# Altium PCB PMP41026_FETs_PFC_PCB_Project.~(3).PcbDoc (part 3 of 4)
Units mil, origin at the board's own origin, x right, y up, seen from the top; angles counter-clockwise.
Board outline 2440.95 x 1417.32 mil, 6 copper layers (Top Layer, Signal Layer 1, Signal Layer 2, Signal Layer 3, Signal Layer 4, Bottom Layer), stack 69.8 mil thick; 61 components, 66 nets, 254 pads, 775 vias.
Unrouted connection lines stored in the file: 2.

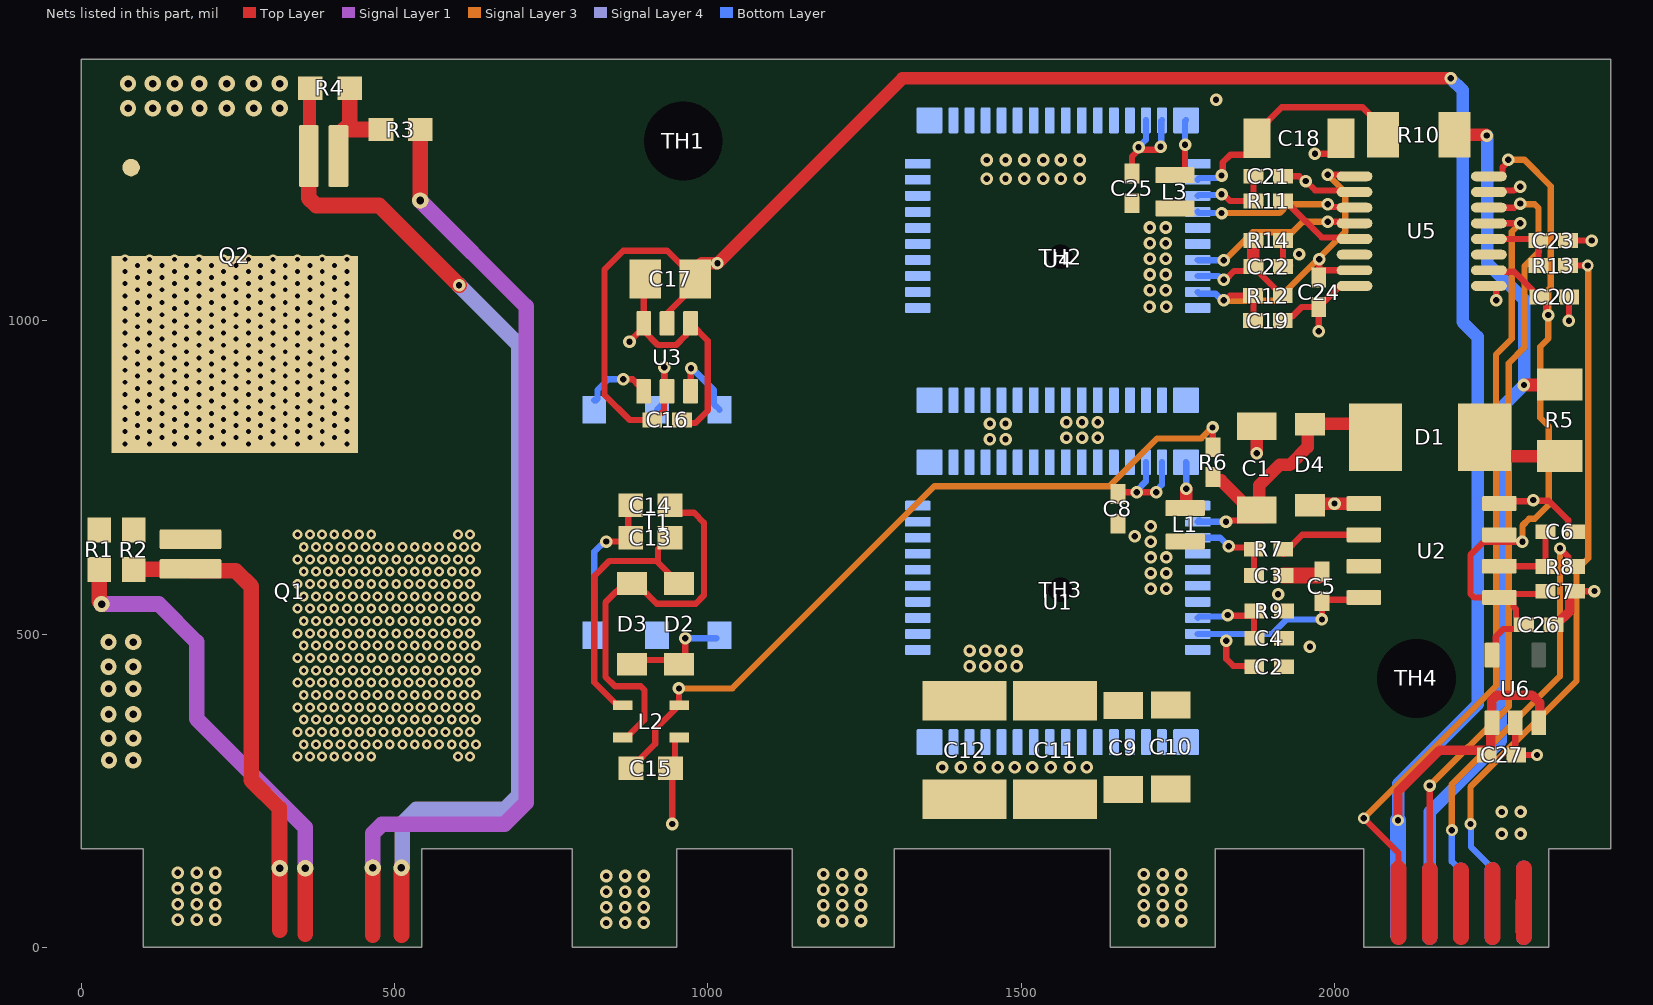
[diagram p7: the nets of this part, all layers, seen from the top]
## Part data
C1 C18: library part CMP-0008692-2, "CAP, CERM, 10 uF, 25 V, +/- 20%, X7R, 1206_190", Cap_Case=1206, Manufacturer=TDK, Supplier Part Number 1=445-6812-1-ND, TempCo=X7R, Tolerance_%=20%, Value1=Unknown, Value2=25V, ValueDisplayed=10uF
C2 C19: library part CMP-0860563-1, "CAP, CERM, 0.22 µF, 16 V,+/- 10%, X7R, 0402", Cap_Case=0402, Manufacturer="Samsung Electro-Mechanics", TempCo=X7R, Tolerance_%=10%, Value2=16V, ValueDisplayed=0.22µF
C3 C4 C6 C21 C22 C23: library part CMP-0006196-2, "CAP, CERM, 100 pF, 50 V, +/- 1%, C0G/NP0, 0402", Cap_Case=0402, Manufacturer=AVX, Supplier Part Number 1=478-3658-1-ND, TempCo=C0G/NP0, Tolerance_%=1%, Value1=Unknown, Value2=50V, ValueDisplayed=100pF
C5 C16 C24: library part CMP-0006297-2, "CAP, CERM, 0.1 uF, 50 V, +/- 10%, X7R, 0402", Alternate Manufacturer="Wurth Elektronik", Alternate PartNumber=885012205037, Cap_Case=0402, Manufacturer=TDK, Supplier Part Number 1=445-5932-1-ND, TempCo=X7R, Tolerance_%=10%, Value1="0.039064 ohm", Value2=50V, ValueDisplayed=0.1uF
C7 C20: library part CMP-0006276-2, "CAP, CERM, 1 uF, 25 V, +/- 10%, X5R, 0402", Alternate Manufacturer=TDK, Alternate PartNumber=C1005X5R1E225K050BC, Cap_Case=0402, Supplier Part Number 1=445-9066-1-ND, TempCo=X5R, Tolerance_%=10%, Value1=Unknown, Value2=25V, ValueDisplayed=1uF
C8 C25: library part CMP-0006716-2, "CAP, CERM, 2.2 uF, 25 V, +/- 10%, X5R, AEC-Q200 Grade 3, 0402", Cap_Case=0402, Manufacturer=MuRata, Supplier Part Number 1=490-12267-1-ND, TempCo=X5R, Tolerance_%=10%, Value1=Unknown, Value2=25V, ValueDisplayed=2.2uF
C9 C10: library part CMP-0084048-1, "CAP, CERM, 0.022 µF, 1000 V,+/- 10%, X7R, AEC-Q200 Grade 1, 1206", Cap_Case=1206, Manufacturer=Kemet, TempCo=X7R, Tolerance_%=10%, Value2=1000V, ValueDisplayed=0.022µF
C11 C12: library part CMP-0009326-2, "CAP, CERM, 0.1 uF, 1000 V, +/- 10%, X7R, 1812", Cap_Case=1812, Manufacturer=Kemet, Supplier Part Number 1=399-6523-1-ND, TempCo=X7R, Tolerance_%=10%, Value1=Unknown, Value2=1000V, ValueDisplayed=0.1uF
C13 C14 C15: library part CMP-0007022-5, "CAP, CERM, 4.7 uF, 35 V, +/- 10%, X5R, 0603", Cap_Case=0603, Manufacturer=TDK, Supplier Part Number 1=445-9064-1-ND, TempCo=X5R, Tolerance_%=10%, Value1="0.003728 ohm", Value2=35V, ValueDisplayed=4.7uF
C17: library part CMP-0008020-2, "CAP, CERM, 4.7 uF, 16 V, +/- 10%, X7R, AEC-Q200 Grade 1, 0805", Cap_Case=0805, Manufacturer=MuRata, Supplier Part Number 1=490-5332-1-ND, TempCo=X7R, Tolerance_%=10%, Value1=Unknown, Value2=16V, ValueDisplayed=4.7uF
C26 C27: library part CMP-0006623-2, "CAP, CERM, 0.1 uF, 6.3 V, +/- 10%, X7R, 0402", Cap_Case=0402, Manufacturer=MuRata, Supplier Part Number 1=GRM155R70J104KA01D-ND, TempCo=X7R, Tolerance_%=10%, Value1=Unknown, Value2=6.3V, ValueDisplayed=0.1uF
D1: library part CMP-0076998-2, "Diode, Schottky, 650 V, 1 A, SMB", Manufacturer="GeneSiC Semiconductor", Value1=1A, Value2=2V
D2 D3: library part CMP-0028524-2, "Diode, Schottky, 20 V, 0.5 A, SOD-123", Manufacturer="ON Semiconductor", Value1=0.5A, Value2=0.385V
D4: library part CMP-0005769-4, "Diode, Zener, 16 V, 500 mW, AEC-Q101, SOD-123", Manufacturer="Diodes Inc.", Power_W=500mW, Value1=0.5W
L1 L3: library part CMP-0089347-1, "4.7µH Unshielded Inductor 1.1A 426mOhm Max 0806 (2016 Metric)", Digikey Part Number=2037-SDEM20161T-4R7MSCT-ND, Manufacturer=Cyntec, Operating Temperature Range="-55°C to +125°C", Test Frequency=1MHz, Tolerance_%=20%
L2: library part CMP-0013161-2, "Coupled inductor, 0.2 A, 0.45 ohm, SMD", Manufacturer=TDK, Supplier Part Number 1=445-8930-1-ND
Q1 Q2: library part CMP-0086487-1, "N-Channel 600V 23A (Tc) 390W (Tc) Surface Mount PG-HSOF-8-2", Manufacturer=Infineon
R1 R3: library part CMP-0022003-4, "RES, 10.0, 1%, 0.1 W, AEC-Q200 Grade 0, 0603", Manufacturer=Vishay-Dale, Power_W=100mW, Supplier Part Number 1=541-10.0HCT-ND, TempCo="100 ppm/C", Tolerance_%=1%, Value2=0.1W, Value_Code=10R0, ValueDisplayed=10.0
R2 R4: library part CMP-0021998-4, "RES, 10.0 k, 1%, 0.1 W, AEC-Q200 Grade 0, 0603", Manufacturer=Vishay-Dale, Power_W=100mW, Supplier Part Number 1=541-10.0KHCT-ND, TempCo="100 ppm/C", Tolerance_%=1%, Value2=0.1W, Value_Code=10k0, ValueDisplayed=10.0k
R5: library part CMP-0018623-3, "RES, 1.8, 5%, 0.25 W, AEC-Q200 Grade 0, 1206", Manufacturer=Vishay-Dale, Power_W=250mW, Supplier Part Number 1=541-1.8ECT-ND, TempCo="200 ppm/C", Tolerance_%=5%, Value2=0.25W, Value_Code=1R80, ValueDisplayed=1.8
R6 R12: library part CMP-0026992-3, "RES, 0, 5%, 0.1 W, AEC-Q200 Grade 0, 0402", Manufacturer=Panasonic, Power_W=100mW, Supplier Part Number 1=P0.0JCT-ND, TempCo="600 ppm/C", Tolerance_%=5%, Value2=0.1W, Value_Code=0000, ValueDisplayed=0
R7 R8 R11 R13: library part CMP-0026738-1, "RES, 49.9, 1%, 0.063 W, 0402", Manufacturer="Yageo America", Power_W=63mW, Supplier Part Number 1=311-49.9LRCT-ND, TempCo="100 ppm/C", Tolerance_%=1%, Value2=0.063W, Value_Code=49R9, ValueDisplayed=49.9
R9 R14: library part CMP-0026162-1, "RES, 20.0 k, 1%, 0.063 W, 0402", Manufacturer=Vishay-Dale, Power_W=63mW, Supplier Part Number 1=541-20.0KLCT-ND, TempCo="100 ppm/C", Tolerance_%=1%, Value2=0.063W, Value_Code=20k0, ValueDisplayed=20.0k
R10: library part CMP-0018748-3, "RES, 0, 5%, 0.25 W, AEC-Q200 Grade 0, 1206", Manufacturer=Panasonic, Power_W=250mW, Supplier Part Number 1=P0.0ECT-ND, TempCo="600 ppm/C", Tolerance_%=5%, Value2=0.25W, Value_Code=0000, ValueDisplayed=0
T1: library part CMP-0030718-1, "Transformer, 475uH, SMT", Manufacturer="Wurth Elektronik", Supplier Part Number 1=732-4458-1-ND, ValueDisplayed=475uH
TH1 TH2 TH3 TH4: library part CMP-0003719-1, "Testpoint", Manufacturer="Texas Instruments", PartNumber=TP_H0.45P0.75
U1 U4: library part CMP-0089968-1, "650-V 30-m? GaN FET with Integrated Driver and Protection", Manufacturer="Texas Instruments", Max Supply Voltage=18V, Min Supply Voltage=7.5V, Nominal Supply Current=540uA, Operating Temperature Range="-40°C to +125°C", Output Voltage=520V
U2: library part CMP-0082403-1, "Automotive, High Speed, Robust EMC Reinforced Single-Channel Digital Isolator, D0008B (SOIC-8)", Alternate Manufacturer="Texas Instruments", Alternate PartNumber=ISO7710FQDRQ1, Operating Temperature Range="-40 to 125 C", Rating=Automotive
U3: library part CMP-0076095-1, "Low-Noise 1 A, 420 kHz Transformer Driver, DBV0006A (SOT-23-6)", Alternate Manufacturer="Texas Instruments", Alternate PartNumber=SN6505BDBVT
U5: library part CMP-0078719-1, "High Speed, Robust EMC Triple-Channel Digital Isolators, DBQ0016A (SSOP-16)", Alternate Manufacturer="Texas Instruments", Alternate PartNumber=ISO7731FDBQ
U6: library part CMP-0065092-2, "Low-Dropout Regulator, DBV0005A (SOT-23-5)", Alternate Manufacturer="Texas Instruments"

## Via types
v1: diameter 15.87, hole 7.87, Top Layer to Bottom Layer, 568 vias
v2: diameter 20, hole 10, Top Layer to Bottom Layer, 151 vias
v3: diameter 26/26/26/26/26/26 (per signal layer), hole 12, Top Layer to Bottom Layer, 32 vias
v4: diameter 20, hole 10, Top Layer to Bottom Layer, tented top, 11 vias
v5: diameter 19, hole 10, Top Layer to Bottom Layer, tented both sides, 7 vias
v6: diameter 20, hole 10, Top Layer to Bottom Layer, tented both sides, 6 vias

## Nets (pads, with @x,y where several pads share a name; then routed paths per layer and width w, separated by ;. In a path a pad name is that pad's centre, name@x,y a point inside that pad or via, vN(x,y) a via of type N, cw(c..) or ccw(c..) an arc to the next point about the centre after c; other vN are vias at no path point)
3V3: C7.1 C20.2 C26.1 U2.1 U2.3 U5.10 U5.16 U6.5 | length 1278.9
  Top Layer w10: U6.5@2252.27,469.85 2257.62,475.2 2257.62,496.04 2269.63,508.05 C26.1@2289.9,508.05 ; U5.16@2258.14,1230.75 2265.92,1230.75 2268.58,1233.4 2268.58,1245.31 2277.61,1254.35 v2(2277.61,1257.05) ; U2.1@2263.55,554.09 2283.63,554.09 2286.11,551.61 2286.11,543.87 2289.9,540.08 C26.1@2289.9,508.05 ; U2.3@2263.55,658.42 U2.3@2280.28,658.42 ; U5.10@2264.53,1078.25 2287.28,1078.25 C20.2@2327.28,1038.25 ; v6(2300.37,647.29) 2238.28,647.29 2217.37,626.38 2217.37,564.28 2223.23,558.42 U2.1@2263.55,558.42 2269.24,564.11 2332.71,564.11 C7.1@2337.03,568.42 ; C26.1@2302.78,514.86 2295.97,508.05 C26.1@2289.9,508.05 ; C20.2@2329.53,1033.25 2336.22,1033.25 2338.03,1031.44 v4@2338.03,1015.53
  Signal Layer 3 w10: v2(2277.61,1257.05) 2303.61,1257.05 2345.59,1215.07 2345.59,1053.42 2341.62,1049.45 v4(2341.62,1009.23) 2341.62,971.74 2328.59,958.72 2328.59,845.31 2342.37,831.53 2342.37,706.27 2320.08,683.98 2310.95,683.98 2300.37,673.4 v6(2300.37,647.29)
5V: C16.1 C17.1 C27.1 T1.5 U3.2 U3.5 U6.1 U6.3 | length 3836.7
  Top Layer w10: C16.1@899.87,841.88 874.87,841.88 834.87,881.88 834.87,1081.88 864.87,1111.88 934.87,1111.88 C17.1@979.87,1066.88 ; C16.1@910.19,836.88 929.87,856.56 U3.2@929.87,881.88 ; U3.2@929.87,904.29 929.87,925.57 v2(930.31,926) ; U3.5@934.87,1011.88 C17.1@979.87,1056.88
  Top Layer w15: v5(2101.62,202.76) 2101.62,248.42 2168.03,314.84 2243,314.84 2245.44,314.84 2249.76,319.15 2249.76,356.56 U6.1@2251.51,358.32 2251.51,393.82 2260.3,402.61 2315.47,402.61 2327.84,390.24 2327.84,359.84 U6.3@2326.31,358.32
  Top Layer w20: C17.1@989.87,1091.88 v4(1015.2,1091.88) 1310.49,1387.17 v2(2185.77,1387.17)
  Bottom Layer w10: T1.5@918.7,858.26 930.31,869.87 v2(930.31,926)
  Bottom Layer w20: v5@2102.37,206.03 2102.37,261.39 2228.64,387.66 2228.64,974.41 2204.72,998.33 2204.72,1368.21 v2(2185.77,1387.17)
  Bottom Layer w25: 2101.62,20.5 v5(2101.62,202.76)
5V_H: C2.2 C5.1 U1.51 U2.8 | length 391.4
  Top Layer w10: v2(1827.66,489.47) 1827.66,460.38 1838.79,449.25 C2.2@1867.87,449.25 ; C2.2@1858.16,447.58 1869.54,447.58 C2.2@1867.87,449.25 ; v4(1980.28,523.42) C5.1@1980.28,548.42 ; C5.1@1980.28,554.8 U2.8@2031.66,554.8 ; C2.2@1867.87,449.25 1858.16,449.25 C2.2@1867.87,449.25
  Bottom Layer w10: U1.51@1781.91,500.31 1829.78,500.31 1901,500.31 1924.11,523.42 v4(1980.28,523.42)
5V_L: C19.2 C24.2 R12.1 U4.51 U5.1 U5.7 | length 572.7
  Top Layer w10: v2(1823.54,1032.74) 1826.25,1032.74 1833.95,1040.44 R12.1@1870.34,1040.44 1870.9,1040.44 1870.9,1013.25 ; C24.2@1975.25,1069.37 1976.03,1070.14 C24.2@1976.03,1080.75 ; v2(1976.03,1098.25) C24.2@1976.03,1080.75 ; v2(1989.53,1233.25) U5.1@2009.53,1233.25 ; U5.7@2032.24,1080.75 C24.2@1976.03,1080.75
  Signal Layer 3 w10: v2@1824.21,1032.06 1907.39,1032.06 2017.37,1142.05 2017.37,1205.4 v2(1989.53,1233.25)
  Bottom Layer w10: U4.51@1781.91,1046.09 1784.79,1043.22 1810.35,1043.22 1821.51,1032.06 v2@1824.21,1032.06
12V: R5.1 R10.1 | length 1518.9
  Top Layer w20: R10.1@2192.16,1297.1 2242.14,1297.1 v6(2243.34,1295.9) ; v2(2302.78,897.67) 2359.5,897.67 R5.1@2360.16,898.32
  Bottom Layer w20: 2152.19,82.36 2152.37,82.55 2152.37,216.06 2265.78,329.47 2265.78,860.68 2303.53,898.42 2303.53,1033.12 2244.09,1092.56 2244.09,1295.14 v6(2243.34,1295.9)
  Bottom Layer w25: 2152.19,16.35 2152.49,124.71
+BRDG_N: R1.1 | length 771.6
  Top Layer w25: R1.1@28.13,603.1 28.13,552.19 32.07,548.25 v3(32.07,547.98) ; 357.42,21.38 v3(357.42,126.06)
  Signal Layer 1 w25: v3(32.07,547.98) 123.37,547.98 183.84,487.51 183.84,364.97 357.42,191.39 v3(357.42,126.06)
+BRDG_P: R3.1 | length 1572.7
  Top Layer w20: v3(540.62,1192.19) v3@540.83,1192.4 ; R3.1@540.83,1305.27 R3.1@541.04,1305.48
  Top Layer w25: 464.96,19.74 v3(464.96,126.88) ; v3@540.83,1192.4 R3.1@540.83,1305.27
  Signal Layer 1 w20: v3(540.62,1192.19) v3@541.4,1191.4
  Signal Layer 1 w25: v3(464.96,126.88) 464.96,181.79 479.61,196.44 675.36,196.44 709.78,230.86 709.78,1023.03 v3@540.94,1191.86
AGND: C6.2 C7.2 C16.2 C17.2 C20.1 C23.2 C26.2 C27.2 U2.4 U3.4 U3.6 U5.9 U5.15 U6.2 | length 1333.4
  Top Layer w10: v4(874.87,966.88) U3.6@889.87,981.88 ; U3.6@897.47,984.28 920.19,961.56 949.56,961.56 U3.4@964.87,976.88 ; U3.6@897.47,996.01 C17.2@897.47,1044.48 ; C16.2@954.87,836.88 979.87,836.88 999.87,856.88 999.87,968.41 U3.4@972.28,996.01 ; U5.9@2249.53,1053.25 2258.49,1053.25 2258.65,1053.09 v2(2258.65,1032.87) ; U2.4@2263.55,708.42 2267.22,712.09 2315.59,712.09 v2(2317.5,714.01) 2318.45,713.06 2342.41,713.06 2373.52,681.96 2373.52,670.24 2380.33,663.42 C6.2@2383.9,663.42 ; U5.15@2269.53,1208.25 2286.44,1208.25 2287.51,1209.31 2288.91,1209.31 2293.91,1214.31 v2(2296.62,1214.31) ; U6.2@2288.91,358.32 2288.91,316.16 C27.2@2290.24,314.84 ; C27.2@2290.58,307.03 v5(2323.49,307.03) ; v2(2374.53,1000.16) C20.1@2374.53,1038.25 ; 2389.53,1128.25 v4(2410.95,1128.25) ; C7.2@2390.07,568.64 2390.17,568.53 2415.08,568.53 v2(2415.19,568.64)
  Top Layer w15: C26.2@2350.02,514.86 2353.96,514.86 2376.02,536.92 2376.02,564.11 2380.33,568.42 C7.2@2384.27,568.42
  Top Layer w25: 2202.29,16.24 2202.29,122.81 ; 2252.43,16.22 2252.43,123.36 ; 2302.78,16.56 2302.78,126.13
  Bottom Layer w25: 2301.97,26 2302.37,126.06 2302.37,16.16
  other v2: 2267.37,181.06 2297.37,181.06 2267.37,216.06 2297.37,216.06 1811.29,1352.94
Bot_FET_FAULT: U5.14 | length 1320.9
  Top Layer w10: 2152.37,124.6 v6(2152.37,258.26) ; U5.14@2246.83,1180.77 2287.37,1180.77 2293.91,1187.31 v6(2296.62,1187.31)
  Top Layer w25: 2152.37,16.16 2152.37,124.6 2152.6,124.83
  Signal Layer 3 w10: v6(2152.37,258.26) 2278.37,384.25 2278.37,932.53 2303.66,957.82 2303.66,1087.41 2325.78,1109.53 2325.78,1180.39 2319.92,1186.25 2297.68,1186.25 v6(2296.62,1187.31)
ISO_12V_H: C15.1 L2.2 R6.1 | length 1216.4
  Top Layer w10: C15.1@877.2,285.76 916.12,324.68 916.12,348.01 L2.2@954.47,386.35 953.7,387.12 v4(953.7,413.26) ; v2(1805.57,829.91) 1806.01,829.47 1806.01,798.61 R6.1@1806.45,798.17
  Signal Layer 3 w10: v4(953.7,413.26) 1038.76,413.26 1361.57,736.06 1640.8,736.06 1657.37,752.64 1717.12,812.39 1787.73,812.39 1805.26,829.91 v2(1805.57,829.91)
NC1: TH1.1
NC2: TH3.1
NC3: TH2.1
NC4: TH4.1
NCT1: T1.2
NCU51: U1.1
NCU61: U4.1
NCU516: U1.16
NCU527: U1.27
NCU543: U1.43
NCU547: U1.47
NCU552: U1.52
NCU616: U4.16
NCU627: U4.27
NCU643: U4.43
NCU647: U4.47
NCU652: U4.52
NetC1_1: C1.1 D1.1 D4.1 R6.2 U1.44 | length 484.8
  Top Layer w10: R6.2@1799.64,744.12 R6.2@1806.45,750.93 ; v4(1827.07,679.45) 1828.93,681.3 1887.52,681.3 C1.1@1896.25,690.03
  Top Layer w20: R6.2@1806.45,750.93 1806.45,746.99 1808.26,745.18 1819.22,745.18 1866.45,697.96 C1.1@1876.29,697.96 1880.42,702.09 1880.42,737.9 1912.83,770.31 1929.09,770.31 1957.26,798.48 1957.26,830.95 D4.1@1961.09,834.78 ; D4.1@1976.14,835.65 D1.1@2053.01,835.65
  Bottom Layer w10: U1.44@1784.79,682.32 U1.44@1781.91,679.45 v4(1827.07,679.45)
NetC3_2: C3.2 R7.1 U1.45 | length 131.7
  Top Layer w10: v2(1831.33,640.11) 1833.24,638.2 1868.16,638.2 R7.1@1870.96,635.4 ; C3.2@1871.66,593.42 R7.1@1871.66,628.42
  Bottom Layer w10: U1.45@1781.91,653.86 1817.58,653.86 v2(1831.33,640.11)
NetC4_2: C4.2 R9.2 U1.50 | length 127.2
  Top Layer w10: v2(1829.78,530.31) 1830.72,529.37 1870.71,529.37 1871.66,528.42 C4.2@1871.66,493.62
  Bottom Layer w10: U1.50@1781.91,525.91 1784.12,528.11 1824.87,528.11 1827.07,530.31 v2(1829.78,530.31)
NetC6_1: C6.1 R8.2 U2.2 | length 129.2
  Top Layer w10: U2.2@2263.55,608.42 2336.49,608.42 R8.2@2337.03,607.89 C6.1@2337.03,663.42
NetC8_1: C8.1 U1.40 U1.41 | length 167.8
  Top Layer w10: C8.1@1654.58,723.48 1657.56,726.46 v2(1684.81,726.46) v2(1715.71,726.46)
  Bottom Layer w10: v2(1684.81,726.46) 1684.81,729.17 1699.23,743.59 U1.40@1699.23,774.33 ; v2(1715.71,726.46) 1715.71,729.17 1724.83,738.29 U1.41@1724.83,774.33
NetC13_1: C13.1 D2.1 L2.3 | length 429.6
  Top Layer w10: L2.3@863.91,386.35 855.61,386.35 818.7,423.26 818.7,592.61 842.83,616.74 915.22,616.74 ; C13.1@935.19,653.86 935.19,650.41 920.19,635.4 920.19,614.53 940.19,594.52 947.58,587.14 D2.1@953.91,580.8
NetC13_2: C13.2 C14.1 T1.3 | length 250.1
  Top Layer w10: v2(837.62,647.75) 870.53,647.75 C13.2@876.64,653.86 ; C13.2@872.2,653.86 872.89,654.55 C14.1@872.89,703.26
  Bottom Layer w10: T1.3@818.7,498.26 818.7,631.53 834.92,647.75 v2(837.62,647.75)
NetC14_2: C14.2 D3.2 L2.4 | length 625.4
  Top Layer w10: L2.4@873.7,338.26 898.7,363.26 898.7,410.91 892.84,416.77 851.77,416.77 836.41,432.12 836.41,550.44 D3.2@873.7,587.73 ; D3.2@893.7,573.26 918.39,548.56 980.68,548.56 993.7,561.58 993.7,677.94 977.9,693.74 945.4,693.74 C14.2@935.88,703.26
NetC18_1: C18.1 R10.2 U4.44 | length 391.1
  Top Layer w10: v2(1820.06,1232.07) 1821.97,1233.98 1821.97,1252.91 1834.24,1265.18 1860.16,1265.18 1876.81,1281.83 1876.81,1301.52 1916.18,1340.89 2045.03,1340.89 2077.99,1307.93 R10.2@2077.99,1297.1
  Bottom Layer w10: U4.44@1781.91,1225.23 1784.79,1228.1 1813.39,1228.1 1817.36,1232.07 v2(1820.06,1232.07)
NetC21_2: C21.2 R11.2 U4.45 | length 137.8
  Top Layer w10: v2(1820.06,1202.07) 1822.77,1202.07 1833.64,1191.2 1868.92,1191.2 1870.96,1193.25 1870.96,1227.47 1870.9,1227.53 C21.2@1865.18,1233.25
  Bottom Layer w10: U4.45@1781.91,1199.64 1783.13,1200.85 1818.84,1200.85 v2(1820.06,1202.07)
NetC22_2: C22.2 R12.2 R14.2 U4.50 | length 199.2
  Top Layer w10: v2(1823.54,1065.84) 1826.25,1065.84 1840.18,1079.78 1864.09,1079.78 C22.2@1870.9,1086.59 1917.05,1040.44 R12.2@1917.59,1040.44 ; 1869.16,1099.99 C22.2@1870.9,1098.25
  Top Layer w20: C22.2@1870.9,1098.25 R14.2@1870.9,1128.25
  Bottom Layer w10: U4.50@1781.91,1071.68 1814.99,1071.68 1821.51,1065.17 v2@1824.21,1065.17
NetC23_1: C23.1 R13.2 U5.12 | length 111.4
  Top Layer w10: U5.12@2246.81,1130.75 C23.1@2323.15,1130.75 ; C23.1@2325.65,1128.25 2325.9,1127.99 R13.2@2325.9,1093.25
NetC25_1: C25.1 U4.40 U4.41 | length 168.5
  Top Layer w10: C25.1@1676.91,1235.14 1676.91,1262.28 1687.56,1272.93 1687.84,1273.21 1722.35,1273.21 v2@1722.63,1273.49
  Bottom Layer w10: v2(1687.56,1277.21) 1699.23,1288.89 U4.40@1699.23,1320.11 ; v2(1722.63,1277.78) 1723.73,1278.87 1723.73,1319.01 U4.41@1724.83,1320.11
NetD1_2: D1.2 R5.2 | length 133.1
  Top Layer w20: D1.2@2239.61,814.39 2269.85,784.15 R5.2@2360.16,784.15
NetD2_2: D2.2 D3.1 T1.1 | length 149.5
  Top Layer w10: D3.1@873.7,458.79 D2.2@943.17,458.79 ; D2.2@963.7,463.26 v2(963.7,493.26)
  Bottom Layer w10: v2(963.7,493.26) T1.1@1013.7,493.26
NetL1_2: L1.2 U1.42 | length 72.9
  Top Layer w10: v2(1763.5,732.03) v2@1765.42,733.94
  Top Layer w20: L1.2@1761.71,701.08 1763.5,702.87 v2(1763.5,732.03)
  Bottom Layer w10: U1.42@1763.21,774.33 1763.49,774.05 v2@1763.49,735.91
NetL3_2: L3.2 U4.42 | length 99.6
  Top Layer w10: L3.2@1745.67,1232.64 1753.92,1232.64 1761.71,1240.43 v2(1761.71,1281.06)
  Bottom Layer w10: v2(1761.71,1281.06) 1761.71,1318.61 U4.42@1763.21,1320.11
NetQ1_1: Q1.1 R1.2 R2.2
NetQ2_1: Q2.1 R3.2 R4.2 | length 127
  Top Layer w25: R4.2@428.02,1371.23 428.02,1314.38 419.13,1305.48 428.02,1305.48 R3.2@476.74,1305.48
NetR7_2: R7.2 U2.6 | length 123.8
  Top Layer w10: R7.2@1918.9,628.42 1948.9,658.42 U2.6@2030.28,658.42
NetR11_1: R11.1 U5.5 | length 119.2
  Top Layer w10: R11.1@1918.21,1193.25 R11.1@1924.53,1193.25 ; R11.1@1924.53,1188.46 1979.74,1133.25 U5.5@2014.53,1133.25
NetT1_4: T1.4 U3.1 | length 97.5
  Top Layer w10: v4(864.87,906.88) 879.87,906.88 U3.1@889.87,896.88
  Bottom Layer w10: T1.4@818.7,873.26 821.71,873.26 823.71,875.26 823.71,889.4 841.19,906.88 v4(864.87,906.88)
NetT1_6: T1.6 U3.3 | length 110.6
  Top Layer w10: v2(973.15,924.5) 972.71,924.06 972.71,902.43 973.26,901.88 U3.3@974.87,901.88
  Bottom Layer w10: v2(973.15,924.5) 974.6,924.5 1009.7,889.4 1009.7,867.25 T1.6@1018.7,858.26
NetU4_46: U4.46 U5.3 | length 262
  Top Layer w10: v2(1989.53,1186.25) 1992.23,1186.25 1996.63,1181.85 2031.14,1181.85 U5.3@2032.24,1180.75
  Signal Layer 3 w10: v2(1820.06,1172.07) 1912.56,1172.07 1926.74,1186.25 v2(1989.53,1186.25)
  Bottom Layer w10: U4.46@1781.91,1174.05 1783.89,1172.07 v2(1820.06,1172.07) v2@1821.97,1170.16
NetU4_49: U4.49 U5.4 | length 264
  Top Layer w10: v2(1989.53,1158.25) U5.4@2019.53,1158.25
  Signal Layer 3 w10: v2@1824.21,1095.92 1869.99,1141.7 1932.97,1141.7 1949.53,1158.25 v2(1989.53,1158.25)
  Bottom Layer w10: U4.49@1781.91,1097.28 1782.59,1096.6 v2(1823.54,1096.6) v2@1824.21,1095.92
Neutral: Q1.2 Q2.9 R2.1 | length 982.2
  Top Layer w10: Q2.9@107.26,946.56 Q2.9@167.88,946.56 ; Q2.9@128.51,946.56 Q2.9@167.88,946.56 ; Q2.9@207.25,946.56 245.05,946.56 Q2.9@167.88,946.56
  Top Layer w25: R2.1@83.8,603.1 84.32,603.62 173.54,603.62 Q1.2@174.06,604.14 177.31,600.89 246.37,600.89 271.01,576.25 271.01,266.78 316.25,221.54 316.25,126.25 v3(316.45,126.06) 316.45,27.07
  other v1: 69.45,803.67 108.82,803.67 148.19,803.67 187.56,803.67 226.93,803.67 266.3,803.67 305.67,803.67 345.04,803.67 384.41,803.67 423.78,803.67 89.14,813.51 128.51,813.51 167.88,813.51 207.25,813.51 246.62,813.51 285.99,813.51 325.36,813.51 364.73,813.51 404.1,813.51 69.45,823.35 108.82,823.35 148.19,823.35 187.56,823.35 226.93,823.35 266.3,823.35 305.67,823.35 345.04,823.35 384.41,823.35 423.78,823.35 89.14,833.19 128.51,833.19 167.88,833.19 207.25,833.19 246.62,833.19 285.99,833.19 325.36,833.19 364.73,833.19 404.1,833.19 69.45,842.48 108.82,842.48 148.19,842.48 187.56,842.48 226.93,842.48 266.3,842.48 305.67,842.48 345.04,842.48 384.41,842.48 423.78,842.48 89.14,852.32 128.51,852.32 167.88,852.32 207.25,852.32 246.62,852.32 285.99,852.32 325.36,852.32 364.73,852.32 404.1,852.32 69.45,862.17 108.82,862.17 148.19,862.17 187.56,862.17 226.93,862.17 266.3,862.17 305.67,862.17 345.04,862.17 384.41,862.17 423.78,862.17 89.14,872.01 128.51,872.01 167.88,872.01 207.25,872.01 246.62,872.01 285.99,872.01 325.36,872.01 364.73,872.01 404.1,872.01 69.45,882.41 108.82,882.41 148.19,882.41 187.56,882.41 226.93,882.41 266.3,882.41 305.67,882.41 345.04,882.41 384.41,882.41 423.78,882.41 89.14,892.25 128.51,892.25 167.88,892.25 207.25,892.25 246.62,892.25 285.99,892.25 325.36,892.25 364.73,892.25 404.1,892.25 69.45,902.09 108.82,902.09 148.19,902.09 187.56,902.09 226.93,902.09 266.3,902.09 305.67,902.09 345.04,902.09 384.41,902.09 423.78,902.09 89.14,911.93 128.51,911.93 167.88,911.93 207.25,911.93 246.62,911.93 285.99,911.93 325.36,911.93 364.73,911.93 404.1,911.93 69.45,921.22 108.82,921.22 148.19,921.22 187.56,921.22 226.93,921.22 266.3,921.22 305.67,921.22 345.04,921.22 384.41,921.22 423.78,921.22 89.14,931.06 128.51,931.06 167.88,931.06 207.25,931.06 246.62,931.06 285.99,931.06 325.36,931.06 364.73,931.06 404.1,931.06 69.45,940.91 108.82,940.91 148.19,940.91 187.56,940.91 226.93,940.91 266.3,940.91 305.67,940.91 345.04,940.91 384.41,940.91 423.78,940.91 89.14,950.75 128.51,950.75 167.88,950.75 207.25,950.75 246.62,950.75 285.99,950.75 325.36,950.75 364.73,950.75 404.1,950.75 69.45,961.15 108.82,961.15 148.19,961.15 187.56,961.15 226.93,961.15 266.3,961.15 305.67,961.15 345.04,961.15 384.41,961.15 423.78,961.15 89.14,970.99 128.51,970.99 167.88,970.99 207.25,970.99 246.62,970.99 285.99,970.99 325.36,970.99 364.73,970.99 404.1,970.99 69.45,980.83 108.82,980.83 148.19,980.83 187.56,980.83 226.93,980.83 266.3,980.83 305.67,980.83 345.04,980.83 384.41,980.83 423.78,980.83 89.14,990.67 128.51,990.67 167.88,990.67 207.25,990.67 246.62,990.67 285.99,990.67 325.36,990.67 364.73,990.67 404.1,990.67 69.45,999.96 108.82,999.96 148.19,999.96 187.56,999.96 226.93,999.96 266.3,999.96 305.67,999.96 345.04,999.96 384.41,999.96 423.78,999.96 89.14,1009.8 128.51,1009.8 167.88,1009.8 207.25,1009.8 246.62,1009.8 285.99,1009.8 325.36,1009.8 364.73,1009.8 404.1,1009.8 69.45,1019.65 108.82,1019.65 148.19,1019.65 187.56,1019.65 226.93,1019.65 266.3,1019.65 305.67,1019.65 345.04,1019.65 384.41,1019.65 423.78,1019.65 89.14,1029.49 128.51,1029.49 167.88,1029.49 207.25,1029.49 246.62,1029.49 285.99,1029.49 325.36,1029.49 364.73,1029.49 404.1,1029.49 69.45,1039.89 108.82,1039.89 148.19,1039.89 187.56,1039.89 226.93,1039.89 266.3,1039.89 305.67,1039.89 345.04,1039.89 384.41,1039.89 423.78,1039.89 89.14,1049.73 128.51,1049.73 167.88,1049.73 207.25,1049.73 246.62,1049.73 285.99,1049.73 325.36,1049.73 364.73,1049.73 404.1,1049.73 69.45,1059.57 108.82,1059.57 148.19,1059.57 187.56,1059.57 226.93,1059.57 266.3,1059.57 305.67,1059.57 345.04,1059.57 384.41,1059.57 423.78,1059.57 89.14,1069.41 128.51,1069.41 167.88,1069.41 207.25,1069.41 246.62,1069.41 285.99,1069.41 325.36,1069.41 364.73,1069.41 404.1,1069.41 69.45,1078.7 108.82,1078.7 148.19,1078.7 187.56,1078.7 226.93,1078.7 266.3,1078.7 305.67,1078.7 345.04,1078.7 384.41,1078.7 423.78,1078.7 89.14,1088.54 128.51,1088.54 167.88,1088.54 207.25,1088.54 246.62,1088.54 285.99,1088.54 325.36,1088.54 364.73,1088.54 404.1,1088.54 69.45,1098.39 108.82,1098.39 148.19,1098.39 187.56,1098.39 226.93,1098.39 266.3,1098.39 305.67,1098.39 345.04,1098.39 384.41,1098.39 423.78,1098.39
  other v2: 153.84,43.94 183.84,43.94 213.84,43.94 153.84,68.94 183.84,68.94 213.84,68.94 153.84,93.94 183.84,93.94 213.84,93.94 153.84,118.94 183.84,118.94 213.84,118.94
  other v3: 44.08,298.58 82.66,298.58 43.29,333.59 82.66,333.59 43.29,372.23 82.66,372.23 43.29,412.55 82.66,412.55 43.29,448.01 82.66,448.01 43.29,487.34 82.66,487.34
PFC_Temp3: U5.13 | length 1315.7
  Top Layer w10: v5(2047.01,206.03) 2102.37,150.67 2102.37,126.06 ; U5.13@2246.81,1155.75 v6(2296.62,1155.75)
  Top Layer w25: 2102.37,16.16 2102.37,126.06
  Signal Layer 3 w10: v5(2047.01,206.03) 2258.26,417.28 2258.26,946.52 2283.23,971.49 2283.23,1142.36 v6(2296.62,1155.75)
PGND: C9.2 C10.2 C11.2 C12.2 C18.2 C19.1 C21.1 C22.1 C24.1 C25.2 L3.1 Q2.2 Q2.3-4-5-6-7-8 R4.1 R14.1 U4.17 U4.18 U4.19 U4.20 U4.21 U4.22 U4.23 U4.24 U4.25 U4.26 U4.28 U4.29 U4.30 U4.31 U4.32 U4.33 U4.34 U4.35 U4.36 U4.37 U4.38 U4.39 U5.2 U5.8 | length 2048.1
  Top Layer w10: C19.1@1917.59,1005.44 1919.4,1007.25 1933.22,1007.25 1948.09,1022.12 C24.1@1975.25,1022.12 ; C22.1@1918.15,1093.25 1918.15,1121.87 R14.1@1919.53,1123.25 ; C21.1@1918.2,1230.75 1944.32,1230.75 1951.82,1223.25 v4(1954.53,1223.25) 1969.53,1208.25 U5.2@2009.53,1208.25 ; C22.1@1924.53,1093.25 C22.1@1929.53,1088.25 ; v4(1969.07,1266.67) C18.2@1993.74,1266.67 ; v2(1975.25,983.25) C24.1@1975.25,1022.12 ; U5.8@2032.24,1055.75 2008.88,1055.75 C24.1@1975.25,1022.12
  Top Layer w20: Q2.2@362.98,1263.12 364.01,1264.15 364.01,1370.21 R4.1@365.03,1371.23 ; v3(510.79,126.88) v3@511.94,128.03
  Top Layer w25: Q2.2@362.98,1263.12 362.98,1195.8 374.7,1184.08 475.52,1184.08 v6(602.72,1056.88) ; 510.79,19.74 v3(510.79,126.88)
  Signal Layer 1 w25: v3(510.79,126.88) v3@510.98,127.07
  Signal Layer 4 w25: v3@511.94,128.03 511.94,197.31 534.52,219.9 675.25,219.9 698.47,243.12 698.47,961.13 v6(602.72,1056.88)
  other v2: 1184.43,42.01 1214.43,42.01 1244.43,42.01 1184.43,67.01 1214.43,67.01 1244.43,67.01 1184.43,92.01 1214.43,92.01 1244.43,92.01 1184.43,117.01 1214.43,117.01 1244.43,117.01 1417.72,448.78 1442.72,448.78 1467.72,448.78 1492.72,448.78 1417.72,473.78 1442.72,473.78 1467.72,473.78 1492.72,473.78 1705.06,1022.4 1731.88,1022.4 1705.73,1049.06 1730.73,1049.06 1705.73,1074.06 1730.73,1074.06 1705.73,1099.06 1730.73,1099.06 1943.74,1106.59 1705.73,1124.06 1730.73,1124.06 1705.73,1149.06 1730.73,1149.06 1445.23,1226.85 1475.23,1226.85 1505.23,1226.85 1535.23,1226.85 1563.61,1226.85 1593.61,1226.85 1445.23,1256.85 1475.23,1256.85 1505.23,1256.85 1535.23,1256.85 1563.61,1256.85 1593.61,1256.85
  other v3: 74.31,1339.52 113.68,1339.52 149.11,1339.52 188.48,1339.52 231.79,1339.52 275.1,1339.52 316.44,1339.52 74.31,1378.89 113.68,1378.89 149.11,1378.89 188.17,1378.89 231.79,1378.89 275.1,1378.89 316.44,1378.89
SW: C1.2 C2.1 C3.1 C4.1 C5.2 C8.2 C15.2 D4.2 L1.1 L2.1 R9.1 U1.17 U1.18 U1.19 U1.20 U1.21 U1.22 U1.23 U1.24 U1.25 U1.26 U1.28 U1.29 U1.30 U1.31 U1.32 U1.33 U1.34 U1.35 U1.36 U1.37 U1.38 U1.39 U2.5 U4.2 U4.3 U4.4 U4.5 U4.6 U4.7 U4.8 U4.9 U4.10 U4.11 U4.12 U4.13 U4.14 U4.15 | length 338.4
  Top Layer w10: v2(943.17,196.85) 943.17,279.79 938.7,284.26 C15.2@940.19,285.76 947.58,293.14 947.58,332.29 950.45,335.17 L2.1@954.47,335.17 ; v2@1705.54,649.28 v2@1707.16,647.65 ; L1.1@1761.43,647.65 L1.1@1761.71,647.94
  Top Layer w20: v2(1876.29,788.56) C1.2@1876.29,831.82 ; D4.2@1961.09,705.84 1963.67,708.42 v2(2000.28,708.42) U2.5@2047.01,708.42
  Top Layer w25: C3.1@1918.9,593.42 C5.2@1975.28,593.42
  other v2: 837.75,38.86 867.75,38.86 897.75,38.86 837.75,63.86 867.75,63.86 897.75,63.86 837.75,88.86 867.75,88.86 897.75,88.86 837.75,113.86 867.75,113.86 897.75,113.86 1910.28,563.42 1706.88,572.36 1731.88,572.36 1706.88,597.36 1731.88,597.36 1706.88,622.36 1731.88,622.36 1706.88,647.36 1681.51,656.14 1706.88,672.36 1450.23,811.06 1475.23,811.06 1572.37,813.27 1597.37,813.27 1622.37,813.27 1450.23,836.06 1475.23,836.06 1572.37,838.27 1597.37,838.27 1622.37,838.27
  other v4: 1961.09,479.99
TTP_HSDRV1: R8.1 | length 750.2
  Top Layer w10: v5(2360.16,636.86) 2373.52,623.5 2373.52,614.7 2379.8,608.42 R8.1@2383.9,608.42
  Signal Layer 3 w10: v5(2187.59,187.01) 2187.59,259.94 2360.16,432.51 v5(2360.16,636.86)
  Bottom Layer w10: v5(2187.59,187.01) 2187.59,137.1 2202.37,122.32 2202.37,111.06
  Bottom Layer w25: 2201.89,16.65 2201.89,122.74
TTP_LSDRV1: R13.1 | length 1297.5
  Top Layer w10: R13.1@2369.53,1088.25 R13.1@2373.15,1088.25 v5(2404.53,1088.25)
  Signal Layer 3 w10: v5(2217.37,196.85) 2217.37,256.06 2386.74,425.43 2386.74,602.46 2405.28,621.01 2405.28,1087.49 v5(2404.53,1088.25)
  Bottom Layer w10: v5(2217.37,196.85) 2218.37,195.85 2218.37,160.06 2252.37,126.06 2252.37,121.06
  Bottom Layer w25: 2252.03,25.55 2252.03,123.29 ; 2252.37,16.16 2252.37,121.06
U2NC7: U2.7
U3NC6: U5.6
U3NC11: U5.11
U5FAULT: U1.46
U5OC: U1.48
U5TEMP: U1.49
U6OC: U4.48
Vbulk1: C9.1 C10.1 C11.1 C12.1 U1.2 U1.3 U1.4 U1.5 U1.6 U1.7 U1.8 U1.9 U1.10 U1.11 U1.12 U1.13 U1.14 U1.15
  other v1: 345.04,304.4 364.73,304.4 383.86,304.4 403.54,304.4 423.78,304.4 443.47,304.4 462.6,304.4 600.95,304.4 620.08,304.4 354.89,324.09 374.57,324.09 393.7,324.09 413.39,324.09 433.63,324.09 453.31,324.09 472.44,324.09 492.13,324.09 512.37,324.09 532.05,324.09 551.18,324.09 570.87,324.09 591.11,324.09 610.79,324.09 629.92,324.09 345.04,343.77 364.73,343.77 383.86,343.77 403.54,343.77 423.78,343.77 443.47,343.77 462.6,343.77 482.28,343.77 502.52,343.77 522.21,343.77 541.34,343.77 561.02,343.77 581.26,343.77 600.95,343.77 620.08,343.77 354.89,363.46 374.57,363.46 393.7,363.46 413.39,363.46 433.63,363.46 453.31,363.46 472.44,363.46 492.13,363.46 512.37,363.46 532.05,363.46 551.18,363.46 570.87,363.46 591.11,363.46 610.79,363.46 629.92,363.46 345.04,383.14 364.73,383.14 383.86,383.14 403.54,383.14 423.78,383.14 443.47,383.14 462.6,383.14 482.28,383.14 502.52,383.14 522.21,383.14 541.34,383.14 561.02,383.14 581.26,383.14 600.95,383.14 620.08,383.14 354.89,402.83 374.57,402.83 393.7,402.83 413.39,402.83 433.63,402.83 453.31,402.83 472.44,402.83 492.13,402.83 512.37,402.83 532.05,402.83 551.18,402.83 570.87,402.83 591.11,402.83 610.79,402.83 629.92,402.83 345.04,422.51 364.73,422.51 383.86,422.51 403.54,422.51 423.78,422.51 443.47,422.51 462.6,422.51 482.28,422.51 502.52,422.51 522.21,422.51 541.34,422.51 561.02,422.51 581.26,422.51 600.95,422.51 620.08,422.51 354.89,442.2 374.57,442.2 393.7,442.2 413.39,442.2 433.63,442.2 453.31,442.2 472.44,442.2 492.13,442.2 512.37,442.2 532.05,442.2 551.18,442.2 570.87,442.2 591.11,442.2 610.79,442.2 629.92,442.2 345.04,461.88 364.73,461.88 383.86,461.88 403.54,461.88 423.78,461.88 443.47,461.88 462.6,461.88 482.28,461.88 502.52,461.88 522.21,461.88 541.34,461.88 561.02,461.88 581.26,461.88 600.95,461.88 620.08,461.88 354.89,481.57 374.57,481.57 393.7,481.57 413.39,481.57 433.63,481.57 453.31,481.57 472.44,481.57 492.13,481.57 512.37,481.57 532.05,481.57 551.18,481.57 570.87,481.57 591.11,481.57 610.79,481.57 629.92,481.57 345.04,501.25 364.73,501.25 383.86,501.25 403.54,501.25 423.78,501.25 443.47,501.25 462.6,501.25 482.28,501.25 502.52,501.25 522.21,501.25 541.34,501.25 561.02,501.25 581.26,501.25 600.95,501.25 620.08,501.25 354.89,520.94 374.57,520.94 393.7,520.94 413.39,520.94 433.63,520.94 453.31,520.94 472.44,520.94 492.13,520.94 512.37,520.94 532.05,520.94 551.18,520.94 570.87,520.94 591.11,520.94 610.79,520.94 629.92,520.94 345.04,540.62 364.73,540.62 383.86,540.62 403.54,540.62 423.78,540.62 443.47,540.62 462.6,540.62 482.28,540.62 502.52,540.62 522.21,540.62 541.34,540.62 561.02,540.62 581.26,540.62 600.95,540.62 620.08,540.62 354.89,560.31 374.57,560.31 393.7,560.31 413.39,560.31 433.63,560.31 453.31,560.31 472.44,560.31 492.13,560.31 512.37,560.31 532.05,560.31 551.18,560.31 570.87,560.31 591.11,560.31 610.79,560.31 629.92,560.31 345.04,579.99 364.73,579.99 383.86,579.99 403.54,579.99 423.78,579.99 443.47,579.99 462.6,579.99 482.28,579.99 502.52,579.99 522.21,579.99 541.34,579.99 561.02,579.99 581.26,579.99 600.95,579.99 620.08,579.99 354.89,599.68 374.57,599.68 393.7,599.68 413.39,599.68 433.63,599.68 453.31,599.68 472.44,599.68 492.13,599.68 512.37,599.68 532.05,599.68 551.18,599.68 570.87,599.68 591.11,599.68 610.79,599.68 629.92,599.68 345.04,619.36 364.73,619.36 383.86,619.36 403.54,619.36 423.78,619.36 443.47,619.36 462.6,619.36 482.28,619.36 502.52,619.36 522.21,619.36 541.34,619.36 561.02,619.36 581.26,619.36 600.95,619.36 620.08,619.36 354.89,639.05 374.57,639.05 393.7,639.05 413.39,639.05 433.63,639.05 453.31,639.05 472.44,639.05 492.13,639.05 512.37,639.05 532.05,639.05 551.18,639.05 570.87,639.05 591.11,639.05 610.79,639.05 629.92,639.05 345.04,658.73 364.73,658.73 383.86,658.73 403.54,658.73 423.78,658.73 443.47,658.73 462.6,658.73 600.95,658.73 620.08,658.73
  other v2: 1695.9,42.01 1725.9,42.01 1755.9,42.01 1695.9,67.01 1725.9,67.01 1755.9,67.01 1695.9,92.01 1725.9,92.01 1755.9,92.01 1695.9,117.01 1725.9,117.01 1755.9,117.01 1374.01,287.21 1404,287.25 1434,287.25 1462.7,287.25 1490,287.25 1518,287.25 1547.37,287.25 1578,287.25 1605,287.25
pads on no net: Q1.9 U6.4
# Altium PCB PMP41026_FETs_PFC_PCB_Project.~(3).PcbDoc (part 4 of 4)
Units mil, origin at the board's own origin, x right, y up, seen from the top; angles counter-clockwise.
Board outline 2440.95 x 1417.32 mil, 6 copper layers (Top Layer, Signal Layer 1, Signal Layer 2, Signal Layer 3, Signal Layer 4, Bottom Layer), stack 69.8 mil thick; 61 components, 66 nets, 254 pads, 775 vias.
Unrouted connection lines stored in the file: 2.

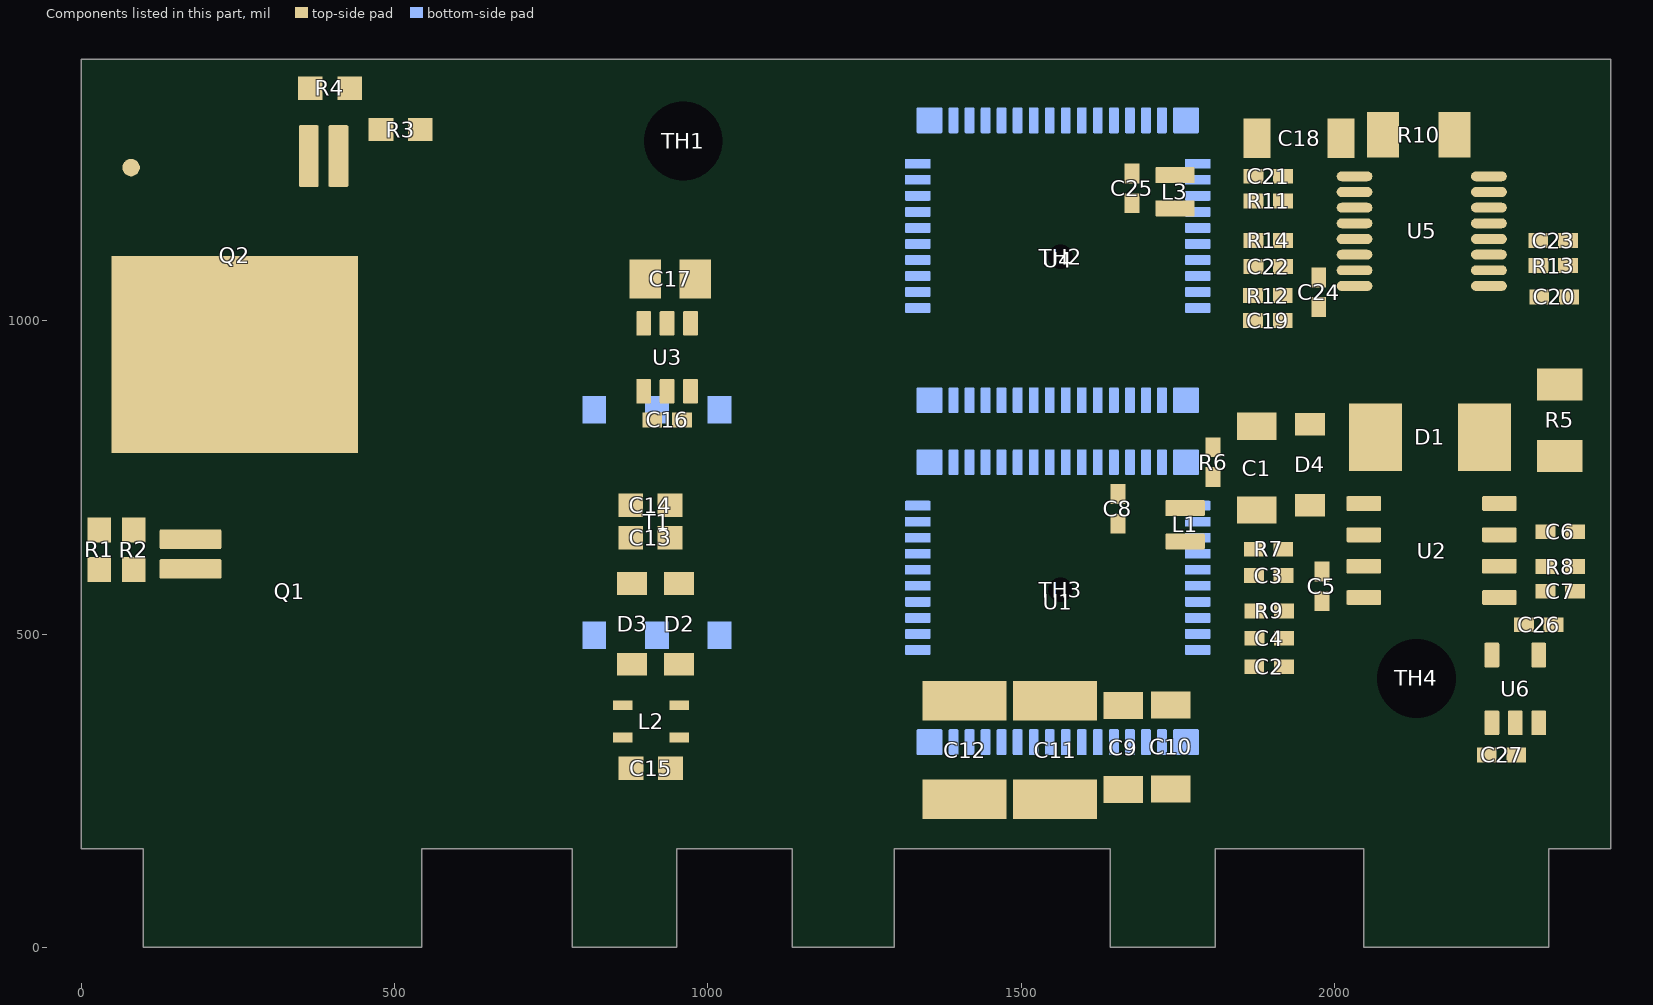
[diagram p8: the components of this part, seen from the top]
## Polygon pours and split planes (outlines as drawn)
Neutral on Bottom Layer "BOTTOM_LAYER_NEUTRAL_P370" (solid, remove dead copper, pour order 370): 163.46,298.58 275.59,186.45 275.59,161.87 99.08,161.87 -0.62,261.56 -0.62,313.36 -0.62,786.44 -0.62,1078.48 44.43,1123.53 426.89,1123.53 464.96,1085.45 464.96,791.11 448.4,774.55 287.6,774.55 163.46,650.42
Neutral on Bottom Layer "BOTTOM_LAYER_NEUTRAL_P365" (solid, pour order 365): 102.36,161.87 102.36,0 275.59,0 275.59,161.87
PGND on Bottom Layer "BOTTOM_LAYER_PGND_P355" (solid, pour order 355): 559.7,1240.16 37.63,1240.16 14.25,1263.54 14.25,1383.09 48.48,1417.32 1616.93,1417.32 1646.46,1387.8 1681.31,1352.94 1681.31,1334.71 1631.2,1284.6 1547.37,1284.6 1547.37,1154.91 1379.56,987.1 812.76,987.1
Vbulk1 on Bottom Layer "BOTTOM_LAYER_VBULK1_P352" (solid, remove dead copper, pour order 352): 761.59,397.68 1270.11,397.68 1330.11,337.68 1602.37,337.68 1602.37,232.68 406.79,232.68 334.17,305.3 334.17,685.77 648.83,685.77 660.94,667.7 660.94,498.33
AGND on Bottom Layer "Bottom Layer-AGND" (solid, pour order 320): 2287.37,126.06 2252.37,161.06 2252.37,236.06 2262.37,246.06 2312.37,246.06 2322.37,236.06 2322.37,136.06 2312.37,126.06
SW on Bottom Layer "Bottom Layer-SW 1" (solid, pour order 319): 1739.66,711.14 1751.01,699.79 1751.01,479.99 1732.15,461.14 1701.51,461.14 1681.51,481.14 1681.51,656.14 1626.51,711.14 1491.2,711.14 1396.51,616.44 1396.51,483.64 1374.01,461.14 1316.7,461.14 1281.51,496.33 1281.51,821.14 1691.51,821.14 1709.01,803.64 1709.01,726.14 1724.01,711.14
SW on Bottom Layer "Bottom Layer-SW" (solid, pour order 318): 1862.37,870.75 1819.56,913.56 1299.07,913.56 1281.51,896 1281.51,774.55 1852.37,774.55 1862.37,784.55
PGND on Bottom Layer "Bottom Layer-PGND 1" (solid, pour order 316): 1134.43,152.01 1134.43,-0.39 1294.43,-0.39 1294.43,152.01
no net on Bottom Layer "Bottom Layer-Vbulk+" (solid, pour order 315): 1642.37,161.06 1642.37,3.66 1807.37,3.66 1807.37,161.06
Vbulk1 on Bottom Layer "MidLayer4-PGND" (solid, pour order 314): 1007.05,201.06 968.68,239.43 968.68,352.53 1725.9,352.53 1807.37,271.06 1807.37,141.06 1792.37,126.06 1792.37,3.66 1657.37,3.66 1657.37,131.06 1642.37,146.06 1642.37,161.06 1602.37,201.06
PGND on Bottom Layer "Bottom Layer-PGND" (solid, pour order 321): 1623.92,987.1 1657.56,1020.74 1657.56,1240.43 1662.91,1245.78 1673.43,1245.78 1681.31,1237.91 1681.31,1000.67 1694.88,987.1 1842.88,987.1 1934.55,895.43 2003.59,895.43 2049.54,941.38 2049.54,1288.47 1992.58,1345.43 1876.29,1345.43 1786.29,1255.43 1705.06,1255.43 1695.06,1265.43 1681.31,1279.18 1681.31,1345.43 1402.56,1345.43 1372.56,1375.43 1316.95,1375.43 1297.07,1355.55 1297.07,1011.88 1321.85,987.1
SW on Bottom Layer "Bottom Layer-SW 2" (solid, pour order 317): 782.75,154.14 782.75,-3.26 947.75,-3.26 947.75,154.14
Neutral on Top Layer "TOP_LAYER_NEUTRAL_P354" (solid, pour order 354): 102.36,161.87 102.36,0 275.59,0 275.59,161.87
AGND on Top Layer "Top Layer-AGND" (solid, pour order 329): 2188.62,101.06 2178.59,111.09 2178.59,131.09 2193.6,146.1 2223.96,146.1 2237.87,161.09 2237.87,221.09 2253.23,236.46 2313.23,236.46 2328.59,221.09 2328.56,124.67 2306.91,101.06
PGND on Top Layer "Top Layer-PGND 2" (solid, pour order 325): 1134.43,157.01 1134.43,-0.39 1294.43,-0.39 1294.43,157.01
Vbulk1 on Top Layer "Top Layer-Vbulk+" (solid, pour order 324): 1642.37,161.06 1642.37,3.66 1807.37,3.66 1807.37,161.06
Vbulk1 on Top Layer "MidLayer4-PGND" (solid, pour order 322): 1327.4,191.09 1316.7,201.79 1316.7,285.74 1337.03,306.06 1771.27,306.06 1807.37,269.96 1807.37,18.66 1792.37,3.66 1657.37,3.66 1649.87,11.16 1649.87,171.06 1629.84,191.09
PGND on Top Layer "TOP_LAYER_PGND_P363" (solid, pour order 363): 335.42,1391.67 335.42,1214.13 321.91,1200.62 37.88,1200.62 19.25,1219.25 19.25,1388.1 37.02,1405.87 321.91,1405.86
NetQ1_1 on Top Layer "TOP_LAYER_NETQ1_1_P350" (solid, remove dead copper, pour order 350): 217.11,666.09 217.11,634.59 109.82,634.59 98.01,646.4 1.55,646.4 1.55,687.35 3.83,689.63 99,689.63 99,685.77 118.68,666.09
PGND on Top Layer "Top Layer-PGND" (solid, pour order 330): 1619.31,490.72 1692.58,417.45 1772.58,417.45 1782.58,407.45 1782.58,362.45 1772.43,352.3 1341.77,350.72 1321.77,370.72 1321.77,460.72 1351.77,490.72
SW on Top Layer "Top Layer-SW 1" (solid, pour order 326): 782.75,153.86 782.75,-3.54 947.75,-3.54 947.75,153.86
PGND on Top Layer "Top Layer-PGND 1" (solid, pour order 328): 1896.09,1105.19 1782.32,1105.19 1782.32,1172.2 1916.57,1172.2 1961.09,1127.68 1961.09,1040.19 1951.09,1030.19 1911.09,1030.19 1901.09,1040.19 1901.09,1100.19
PGND on Top Layer "Top Layer-PGND 1" (solid, pour order 327): 1765.24,1205.16 1793.42,1176.97 1793.42,1100.11 1770.24,1076.92 1770.24,1025.16 1745.24,1000.16 1680.24,1000.16 1660.24,1020.16 1660.24,1195.16 1670.24,1205.16
SW on Top Layer "Top Layer-SW" (solid, pour order 323): 1770.24,692.49 1642.37,692.49 1642.37,658.46 1668.98,631.85 1668.98,560.46 1684.58,544.86 1779.58,544.86 1864.58,544.86 1894.58,514.86 1894.58,433.14 1942.79,433.07 1972.05,462.34 1972.05,482.25 1939.58,525.54 1939.58,586.3 1922.8,603.08 1892.64,572.92 1848.34,572.92 1799.41,621.85 1799.41,721.66
Neutral on Top Layer "TOP_LAYER_NEUTRAL_P373" (solid, remove dead copper, pour order 373): 15.29,261.21 217.11,261.56 226.93,271.39 226.93,568.99 223.28,572.65 129.74,572.65 82.5,525.4 41.69,525.4 15.29,499.01
Neutral on Signal Layer 4 "SIGNAL_LAYER_4_NEUTRAL_P372" (solid, remove dead copper, pour order 372): 99.01,180.73 20.66,259.08 20.66,1087.69 35.32,1102.36 442.95,1102.36 464.96,1080.35 464.96,808.4 275.59,619.03 275.59,134.78 99.01,134.78
Neutral on Signal Layer 4 "SIGNAL_LAYER_4_NEUTRAL_P368" (solid, pour order 368): 102.36,161.87 102.36,0 275.59,0 275.59,161.87
PGND on Signal Layer 4 "SIGNAL_LAYER_4_PGND_P359" (solid, pour order 359): 13.46,1417.32 1515.48,1417.32 1617.37,1315.43 1617.37,1197.86 1243.4,823.89 1149.25,823.89 951.26,1021.88 777.98,1021.88 575.8,1224.06 14.25,1224.06 14.25,1417.32
AGND on Signal Layer 4 "MidLayer1-AGND" (solid, pour order 336): 2431.1,228.77 2342.37,140.04 2342.37,101.06 2342.37,3.66 2062.37,3.66 2062.37,255.69 2187.21,380.52 2187.21,1407.32 2410.95,1407.32 2431.1,1387.17
PGND on Signal Layer 4 "MidLayer4-PGND 1" (solid, pour order 335): 1162.37,1216.06 1134.43,1188.12 1134.43,389.01 1162.72,360.72 1434.88,360.72 1525.59,451.43 1525.59,1177.84 1487.37,1216.06
PGND on Signal Layer 4 "MidLayer4-PGND 2" (solid, pour order 332): 1134.43,3.66 1134.43,611.06 1387.56,611.06 1387.56,407.25 1289.44,309.13 1289.44,3.66
SW on Signal Layer 4 "MidLayer1-SW" (solid, pour order 333): 2012.37,513.61 1959.83,461.06 1743.79,461.06 1677.37,527.48 1677.37,664.5 1739.01,726.14 2004.75,726.14 2012.37,718.51 2012.37,576.06
Vbulk1 on Signal Layer 4 "MidLayer4-PGND" (solid, pour order 337): 1367.89,306.06 1351.77,289.95 1351.77,217.18 1367.89,201.06 1619.87,201.06 1656.78,164.16 1656.78,3.66 1793.42,3.66 1793.42,285.01 1772.37,306.06
PGND on Signal Layer 4 "MidLayer1-PGND" (solid, pour order 334): 1679.08,946.5 1707.18,918.4 1979.13,918.4 2012.37,951.65 2012.37,1176.06 1927.37,1261.06 1732.89,1261.06 1679.08,1207.26
Neutral on Top Solder (solid): 103.03,162.03 268.03,162.03 268.03,7.03 265.63,4.63 103.03,4.63
no net on Top Solder (solid): 1134.43,157.01 1294.43,157.01 1294.43,-0.39 1134.43,-0.39
no net on Top Solder (solid): 1642.37,161.06 1807.37,161.06 1807.37,3.66 1642.37,3.66
no net on Top Solder (solid): 781.01,154.82 946.01,154.82 946.01,-0.18 943.61,-2.58 781.01,-2.58
Neutral on Signal Layer 2 "SIGNAL_LAYER_2_NEUTRAL_P371" (solid, remove dead copper, pour order 371): 99.01,169.85 20.66,248.2 20.66,1096.68 47.51,1123.53 475.17,1123.53 492.13,1106.57 492.13,847.06 275.59,630.53 275.59,134.78 99.01,134.78
Neutral on Signal Layer 2 "SIGNAL_LAYER_2_NEUTRAL_P366" (solid, pour order 366): 102.36,161.87 102.36,0 275.59,0 275.59,161.87
PGND on Signal Layer 2 "SIGNAL_LAYER_2_PGND_P361" (solid, pour order 361): 36.71,1240.16 36.71,1398.55 409.57,1398.55 409.57,1240.16
Vbulk1 on Signal Layer 2 "MidLayer4-PGND" (solid, pour order 342): 1385.26,201.06 1351.77,234.55 1351.77,295.57 1382.27,326.06 1752.37,326.06 1807.42,271.02 1807.42,3.66 1649.87,3.66 1649.87,171.06 1619.87,201.06
AGND on Signal Layer 2 "MidLayer2-AGND" (solid, pour order 340): 810.9,831.47 797.89,844.48 797.89,1307.08 908.14,1417.32 1897.37,1417.32 1897.37,1306.06 1322.37,1306.06 999.87,983.56 999.87,864.9 966.44,831.47
AGND on Signal Layer 2 "MidLayer1-AGND" (solid, pour order 339): 2440.94,240.3 2342.37,141.73 2342.37,3.66 2062.37,3.66 2062.37,276.06 2186.09,399.78 2186.09,1229 2109.03,1306.06 1883.91,1306.06 1883.91,1403.08 2415.19,1403.08 2440.94,1377.32
SW on Signal Layer 2 "MidLayer3-SW 1" (solid, pour order 338): 943.17,174.36 943.17,0 797.24,0 797.24,462.67 1196.74,862.17 1621.44,862.17 1642.37,841.24 1642.37,803.56 1627.37,788.56 1557.37,788.56 997.37,228.56
SW on Signal Layer 2 "MidLayer1-SW" (solid, pour order 341): 1673.24,455.53 1658.65,470.12 1658.65,672.05 1699.52,712.92 1791.91,712.92 1910.51,831.53 1965.39,831.53 2012.37,784.55 2012.37,756.06 2012.37,576.06 2012.37,518.56 1949.34,455.53
PGND on Signal Layer 1 "MidLayer1-PGND" (solid, pour order 357): 1701.92,1206.06 1669.28,1173.42 1669.28,988.01 1729.03,928.26 1988.99,928.26 2012.37,951.65 2012.37,1176.06 1982.37,1206.06
Neutral on Signal Layer 1 "SIGNAL_LAYER_1_NEUTRAL_P369" (solid, pour order 369): 102.36,161.87 102.36,0 275.59,0 275.59,161.87
PGND on Signal Layer 1 "SIGNAL_LAYER_1_PGND_P362" (solid, pour order 362): 19.25,1224.06 19.25,1398.55 374.9,1398.55 374.9,1224.06
AGND on Signal Layer 1 "MidLayer1-AGND" (solid, pour order 358): 2431.1,228.77 2342.37,140.04 2342.37,3.66 2062.37,3.66 2062.37,276.06 2077.37,291.06 2186.09,399.78 2186.09,1221.79 2090.93,1316.95 1296.39,1316.95 979.87,1000.44 979.87,844.9 966.44,831.47 810.9,831.47 797.24,845.13 797.24,1306.43 893.89,1403.08 2415.19,1403.08 2431.1,1387.17
Vbulk1 on Signal Layer 1 "MidLayer4-PGND" (solid, pour order 343): 1642.37,161.06 1602.37,201.06 1594.87,201.06 1359.69,201.06 1359.69,326.06 1752.37,326.06 1807.42,271.02 1807.42,3.66 1642.37,3.66
SW on Signal Layer 1 "MidLayer1-SW" (solid, pour order 344): 1891.59,831.53 1984.43,831.53 2012.37,803.58 2012.37,518.56 1949.34,455.53 1673.24,455.53 1658.65,470.12 1658.65,686.08 1688.65,716.08 1776.15,716.08
PGND on Signal Layer 1 "MidLayer1-PGND" (solid, pour order 356): 1092.52,220.74 1148.56,164.7 1148.56,-0.39 1282.37,-0.39 1282.37,798.42 1555.01,1071.06 1617.37,1133.42 1617.37,1257.3 1596.9,1277.78 1425.85,1277.77 1092.52,944.46
Neutral on Bottom Solder (solid): 101.83,162.03 266.83,162.03 266.83,4.63 101.83,4.63
no net on Bottom Solder (solid): 1134.43,157.01 1294.43,157.01 1294.43,-0.39 1134.43,-0.39
no net on Bottom Solder (solid): 1642.37,161.06 1807.37,161.06 1807.37,3.66 1642.37,3.66
no net on Bottom Solder (solid): 781.01,154.82 946.01,154.82 946.01,-2.58 781.01,-2.58
Neutral on Signal Layer 3 "SIGNAL_LAYER_3_NEUTRAL_P367" (solid, pour order 367): 102.36,161.87 102.36,0 275.59,0 275.59,161.87
Vbulk1 on Signal Layer 3 "SIGNAL_LAYER_3_VBULK1_P364" (solid, remove dead copper, pour order 364): 1247.37,394.08 1309.46,331.99 1309.46,280.2 1230.32,201.05 1009.37,201.05 981.86,228.56 391.19,228.56 319.18,300.58 319.18,674.1 335.42,690.34 630.27,690.34 672.04,648.57 672.04,557.98 835.93,394.08
PGND on Signal Layer 3 "SIGNAL_LAYER_3_PGND_P360" (solid, pour order 360): 14.25,1224.06 14.25,1403.08 409.57,1403.08 409.57,1224.06
Vbulk1 on Signal Layer 3 "MidLayer4-PGND" (solid, pour order 345): 1642.37,161.06 1602.37,201.06 1212.35,201.05 1207.37,206.03 1207.37,361.06 1212.88,366.57 1711.87,366.57 1807.42,271.02 1807.42,3.66 1642.37,3.66

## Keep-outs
Keep-Out Layer:
  text ".Layer_Name" at 577,-858.49 h60

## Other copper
Top Layer:
  text ".Layer_Name" at 577,-858.49 h60
Bottom Layer:
  pour cut-out: 835.51,1243.34 ccw(c963.12,1288.64) 1090.74,1333.95 ccw(c963.12,1288.64)
  text ".Layer_Name" at 577,-858.49 h60

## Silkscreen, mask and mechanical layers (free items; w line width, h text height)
Top Overlay:
  lines w10: 2407.8,494.12 2407.8,532.12
  text ".Layer_Name" at 577,-858.49 h60
Bottom Overlay:
  lines w10: 19.68,1337.32 19.68,1417.32 99.68,1417.32 ; 628.66,275.59 708.66,275.59 708.66,355.59 ; 2250.06,1416.96 2332.68,1417.32 2333.03,1337.32 ; 2253.07,275.59 2333.07,275.59 2333.04,355.59
  text ".Layer_Name" at 577,-858.49 h60
Top Paste:
  text ".Layer_Name" at 577,-858.49 h60
Bottom Paste:
  text ".Layer_Name" at 577,-858.49 h60
Top Solder:
  rectangle: 494.46,7.09 525.95,135.33
  rectangle: 448.63,7.09 480.13,135.33
  rectangle: 341.96,7.09 373.46,135.33
  rectangle: 300.99,7.09 332.49,135.33
  rectangle: 2086.1,3.56 2117.6,131.81
  rectangle: 2136.1,3.56 2167.6,131.81
  rectangle: 2186.1,3.56 2217.6,131.81
  rectangle: 2236.1,3.56 2267.6,131.81
  rectangle: 2286.1,3.56 2317.6,131.81
  region: 300.05,1312.21 300.05,1213.79 331.54,1213.79 331.54,1312.21
  region: 252.8,1312.21 252.8,1213.79 284.3,1213.79 284.3,1312.21
  region: 205.56,1312.21 205.56,1213.79 237.05,1213.79 237.05,1312.21
  region: 158.31,1312.21 158.31,1213.79 189.81,1213.79 189.81,1312.21
  region: 111.07,1312.21 111.07,1213.79 142.57,1213.79 142.57,1312.21
  rectangle: 63.83,1213.79 315.78,1233.47
  region: 63.83,1312.21 63.83,1213.79 95.32,1213.79 95.32,1312.21
  region: 223.54,320.68 223.54,572.63 203.86,572.63 203.86,320.68
  rectangle: 124.79,541.14 223.21,572.64
  rectangle: 124.79,493.9 223.21,525.4
  rectangle: 124.79,446.66 223.21,478.15
  rectangle: 124.79,399.41 223.21,430.91
  rectangle: 124.79,304.76 223.21,336.26
  rectangle: 124.79,351.77 223.21,383.27
  text ".Layer_Name" at 577,-858.49 h60
  text ".Layer_Name" at 577,-858.49 h60
Bottom Solder:
  rectangle: 494.46,7.09 525.95,135.33
  rectangle: 448.63,7.09 480.13,135.33
  rectangle: 341.96,7.09 373.46,135.33
  rectangle: 300.99,7.09 332.49,135.33
  rectangle: 2086.1,3.56 2117.6,131.81
  rectangle: 2186.1,3.56 2217.6,131.81
  rectangle: 2286.1,3.56 2317.6,131.81
  rectangle: 2236.1,3.56 2267.6,131.81
  rectangle: 2136.1,3.56 2167.6,131.81
  rectangle: 316.44,285.18 672.04,690.34
  rectangle: 20.66,786.44 462.6,1123.53
  text ".Layer_Name" at 577,-858.49 h60
Drill Guide:
  text ".Layer_Name" at 577,-858.49 h60
M1 Board Outline:
  lines w10: 99.01,3.36 99.01,155.76 97.28,157.48 0,157.48 0,1417.32 2440.94,1417.32 2440.94,157.48 2342.49,157.48 2342.37,157.36 2342.37,0 2051.04,0 2047.47,3.56 2047.37,3.66 2047.37,157.36 1807.37,157.36 1807.37,0 1646.03,0 1642.37,3.66 1642.37,154.81 1639.71,157.48 1309.87,157.48 1298.13,157.48 ; 102.36,0 542.81,0 542.81,157.48 700.46,157.48 783.76,157.48 783.76,0 950.5,0 950.5,161.06 ; 956.04,157.01 1134.43,157.01 ; 1135,156.26 1135,0 1297.37,0 1297.37,156.72
  text ".Layer_Name" at 577,-858.49 h60
M2 Board Dimensions:
  rectangle: 0,-275 125,-150
  rectangle: 125,-400 500,-275
  lines w7: 0,-275 1000,-275 ; 125,-400 125,-150 ; 250,-400 250,-150 ; 500,-400 500,-150 ; 750,-400 750,-150 ; 0,-400 1000,-400 1000,-150 0,-150 0,-400
  text ".Layer_Name" at 577,-858.49 h60
M3 3D STEP Top:
  text ".Layer_Name" at 577,-858.49 h60
M4 3D STEP Bottom:
  text ".Layer_Name" at 577,-858.49 h60
M5 Assembly Top:
  lines w10: -292,-930.17 6308,-930.17 ; -292,-726.83 6310,-726.83 ; -292,-523.5 -292,-1133.5 3713,-1133.5 6310,-1133.5 6310,-523.5 -291.5,-523.5 -291.5,-1133.5 1284,-1133.5 ; 2173,-1133.5 2173,-523.5 ; 3440,-726.83 3440,-523.5 ; 4280,-726.83 4280,-523.5 ; 4902,-1140 4902,-937.17
  text "COMPONENTS MARKED 'DNP' SHOULD NOT BE POPULATED." at 1153.5,-318.5 h60
  text "ASSEMBLY VARIANT:" at 1153,-434 h60
  text ".VariantName" at 2189,-434 h60
  text "PCB VIEWED FROM TOP SIDE" at -228.5,-655.67 h60
  text "BOARD #:" at 2248,-655.67 h60
  text ".PRJ_Number" at 2793.5,-655.67 h60
  text "REV:" at 3638,-655.67 h60
  text ".PCB_Rev" at 3929.5,-655.67 h60
  text "SVN REV:" at 4476,-655.67 h60
  text ".VersionControl_RevNumber" at 4982,-655.67 h60
  text "TID #:" at 2248,-859 h60
  text ".TID" at 2793.5,-859 h60
  text "PLOT NAME =" at -228.5,-1064.34 h60
  text ".plot_File_Name" at 577,-1064.34 h60
  text "GENERATED    :" at 2250,-1064.34 h60
  text ".Print_Date" at 3119.5,-1064.34 h60
  text ".Print_Time" at 3848.5,-1064.34 h60
  text "TEXAS INSTRUMENTS" at 5113,-1064.34 h60
M6 Assembly Bottom:
  lines w10: -292.5,-727.33 6309.5,-727.33 ; -290.5,-930.67 6309.5,-930.67 ; 1115.5,-1140.5 1115.5,-937.67 ; 1737.5,-727.33 1737.5,-524 ; 2577.5,-727.33 2577.5,-524 ; 3844.5,-1134 3844.5,-524 ; 4733.5,-1134 6309,-1134 6309,-524 -292.5,-524 -292.5,-1134 2304.5,-1134 6309.5,-1134 6309.5,-524
  text "COMPONENTS MARKED 'DNP' SHOULD NOT BE POPULATED." at 6102,-318 h60
  text ".VariantName" at 5058,-434 h60
  text "ASSEMBLY VARIANT:" at 6097,-434 h60
  text ".VersionControl_RevNumber" at 1035.5,-656.17 h60
  text "SVN REV:" at 1541.5,-656.17 h60
  text ".PCB_Rev" at 2088,-656.17 h60
  text "REV:" at 2379.5,-656.17 h60
  text ".PRJ_Number" at 3224,-656.17 h60
  text "BOARD #:" at 3769.5,-656.17 h60
  text "PCB VIEWED FROM BOTTOM SIDE" at 6246,-656.17 h60
  text ".TID" at 3224,-859.5 h60
  text "TID #:" at 3769.5,-859.5 h60
  text "TEXAS INSTRUMENTS" at 904.5,-1064.84 h60
  text ".Print_Time" at 2169,-1064.84 h60
  text ".Print_Date" at 2898,-1064.84 h60
  text "GENERATED    :" at 3767.5,-1064.84 h60
  text ".plot_File_Name" at 5440.5,-1064.84 h60
  text "PLOT NAME =" at 6246,-1064.84 h60
M9 Title Sheet:
  drawing of 57 lines, arcs and shapes, not listed
  text "1" at 739.84,8036.5 h70
  text "2" at 3235.5,8036.5 h70
  text "3" at 5724.84,8036.5 h70
  text "4" at 8231.51,8036.5 h70
  text "5" at 10730.5,8036.5 h70
  text "6" at 13235.5,8036.5 h70
  text "A" at -416.5,6893.5 h70
  text "A" at 14383.5,6893.5 h70
  text "B" at -416.5,4513.5 h70
  text "B" at 14383.5,4513.5 h70
  text "C" at -416.5,2138.5 h70
  text "C" at 14383.5,2138.5 h70
  text "PROJECT TITLE:" at 11343.5,277.5 h45
  text ".PRJ_Title" at 11393.5,144.17 h70
  text "DESIGNED FOR:" at 11343.5,-23.5 h45
  text ".PRJ_Customer" at 11393.5,-163.5 h70
  text "D" at -416.5,-231.5 h70
  text "D" at 14383.5,-231.5 h70
  text "FILE NAME:" at 11343.5,-323.5 h45
  text ".PCB_File_Name_No_Path" at 11393.5,-443.5 h70
  text "Texas Instruments (TI) and/or its licensors do not warrant the accuracy or completeness of this specification" at 6374,-605.34 h45
  text "ENGINEER:" at 11343.5,-613.5 h45
  text "LAYOUT BY:" at 12848.5,-613.5 h45
  text "or any information contained therein. TI and/or its licensors do not warrant that this design will meet" at 6329.01,-718 h45
  text ".PRJ_Engineer" at 11393.5,-768.49 h70
  text ".PCB_Layout" at 12899,-768.49 h70
  text "the specifications, will be suitable for your application or fit for any particular purpose, or will operate in" at 6329.01,-830.67 h45
  text ".Layer_Name" at 577,-858.49 h60
  text "ALTIUM DESIGNER VERSION:" at 12848.5,-923.5 h45
  text "an implementation. TI and/or its licensors do not warrant that the design is production worthy. You should" at 6329.01,-943.33 h45
  text "completely validate and test your design implementation to confirm the system functionality for your application." at 6374,-1056 h45
  text ".print_Scale" at 11393.5,-1056.83 h70
  text ".Application_BuildNumber" at 12899,-1056.83 h70
  text "1" at 739.84,-1263.5 h70
  text "2" at 3235.5,-1263.5 h70
  text "3" at 5724.84,-1263.5 h70
  text "4" at 8231.51,-1263.5 h70
  text "5" at 10730.5,-1263.5 h70
  text "6" at 13235.5,-1263.5 h70
M10 Fab Notes:
  drawing of 189 lines, arcs and shapes, not listed
  text "DESIGN INFORMATION" at 12382.02,6356.17 h60
  text "MIN. TRACK WIDTH:" at 11737.46,6224.05 h60
  text "8" at 12833.7,6224.05 h60
  text "MIL" at 12988.46,6224.05 h60
  text "7.874" at 12667.32,6102.36 h60
  text "MIN. CLEARANCE:" at 11737.46,6099.92 h60
  text "MIL" at 12988.46,6099.92 h60
  text "MIN. VIA PAD SIZE:" at 11737.46,5975.8 h60
  text "24" at 12803.71,5975.8 h60
  text "MIL" at 12988.46,5975.8 h60
  text "0.05mm (2MIL)" at 12432.46,5845.9 h60
  text "MINIMUM ANNULAR RING" at 11408.23,5837.67 h60
  text "EXTERNAL" at 13140.46,5837.67 h60
  text "PER" at 11608.23,5727.55 h60
  text "IPC-D-275 CLASS 2 LEVEL C" at 11828.23,5727.54 h60
  text "MIL, HOLES" at 13316.46,5627.07 h60
  text "+/-" at 12924,5618.48 h60
  text "+/-" at 13778,5618.48 h60
  text "REGISTRATION TOLERANCES:" at 11408.23,5617.42 h60
  text "METAL" at 12608,5617.42 h60
  text "5" at 13184.2,5617.42 h60
  text "3" at 14017.2,5617.42 h60
  text "MIL" at 14133.46,5617.42 h60
  text "HOLE SIZE TOLERANCE (UNLESS OTHERWISE SPECIFIED):" at 11408.23,5519.1 h60
  text "+/-" at 13778,5516.23 h60
  text "3" at 14017.2,5515.17 h60
  text "MIL" at 14133.46,5515.17 h60
  text "MATERIAL:" at 11333.46,5377.52 h60
  text "FR-4 High Tg" at 12319.9,5249 h60
  text "X" at 12175.46,5241.01 h60
  text "FR-408" at 11754.46,5236.49 h60
  text "OTHER" at 13242.46,5236.49 h60
  text "62 MIL (1.6mm) +/-10%" at 12074.56,5093.46 h60
  text "X" at 11954.46,5091.01 h60
  text "THICKNESS:" at 11408.23,5085.24 h60
  text "OTHER" at 13359.46,5085.24 h60
  text "TOLERANCE:" at 11408.23,4946.92 h60
  text "X" at 12256.46,4946.92 h60
  text "ANSI IPC-6012 TYPE 3 CLASS 2" at 12434.48,4946.92 h60
  text "OTHER +/-" at 12434.46,4802.73 h60
  text "BOW & TWIST:" at 11408.23,4657.54 h60
  text "X" at 12256.46,4657.54 h60
  text "ANSI IPC-6012 TYPE 3 CLASS 2" at 12434.48,4657.54 h60
  text "OTHER +/-" at 12434.46,4510.85 h60
  text "DRILLING:" at 11333.46,4380.23 h60
  text "NC_DRILL FILES" at 13094.46,4275.04 h60
  text "REFERENCE:" at 11408.23,4271.1 h60
  text "X" at 12065.46,4271.01 h60
  text "AS SHOWN" at 12243.46,4271.1 h60
  text "X" at 12966.46,4271.1 h60
  text "OTHER" at 13392.46,4128.85 h60
  text "PTH COPPER THICKNESS:" at 11407.91,4125.32 h60
  text "X" at 12547.14,4125.32 h60
  text "20-30 um" at 12675.14,4125.32 h60
  text "BOARD FINISH:" at 11333.46,3977.73 h60
  text "SILKSCREEN:" at 11488.68,3867.6 h60
  text "X" at 12446.46,3867.6 h60
  text "TOP" at 12563.46,3867.6 h60
  text "X" at 12956.46,3867.6 h60
  text "BOTTOM" at 13074.46,3867.6 h60
  text "SILKSCREEN COLOR:" at 11488.68,3712.41 h60
  text "X" at 12445.46,3712.41 h60
  text "WHITE" at 12563.46,3712.41 h60
  text "OTHER" at 13074.46,3712.41 h60
  text "X" at 12576.46,3568.96 h60
  text "GREEN" at 12694.46,3568.96 h60
  text "OTHER" at 13312.46,3568.96 h60
  text "SOLDER RESIST COLOR:" at 11488.68,3562.1 h60
  text "X" at 12576.46,3414.71 h60
  text "MATTE" at 12694.46,3414.71 h60
  text "SEMI-GLOSS" at 13312,3414.07 h60
  text "IMMERSION GOLD (ENIG)" at 12394.46,3241.94 h60
  text "ENEPIG" at 13732,3234.72 h60
  text "SURFACE FINISH:" at 11333.46,3233.72 h60
  text "X" at 12216.46,3233.72 h60
  text "IMM. TIN/SILVER OR EQUIV" at 11663,3096.4 h60
  text "OTHER" at 13094.46,3092.47 h60
  text "ARRAY/PANEL:" at 11333.46,2937.09 h60
  text "CUT AND TRIM PER M1 BOARD OUTLINE" at 12394.46,2928.87 h60
  text "N.C. ROUTE" at 12394.46,2792.9 h60
  text "X" at 13082.46,2792.9 h60
  text "V. SCORE" at 13260.46,2792.9 h60
  text "CERTIFICATION:" at 11333.46,2663.77 h60
  text "MATERIALS AND WORKMANSHIP FOR ALL PCBS" at 12058.46,2663.77 h60
  text "TO MEET OR EXCEED THE REQUIREMENTS OF:" at 12058.46,2569.71 h60
  text "X" at 11695.97,2441.08 h60
  text "ANSI IPC-A-600F CLASS ->" at 11823.96,2441.08 h60
  text "X" at 13471.97,2441.08 h60
  text "2" at 13581.96,2441.08 h60
  text "1" at 13266.96,2439.58 h60
  text "3" at 13935.96,2439.58 h60
  text "X" at 12507.97,2293.39 h60
  text "RoHS" at 12635.96,2293.39 h60
  text "OTHER" at 13280.36,2293.39 h60
  text "PER ORDER" at 13677.42,2293.39 h60
  text "ALL BOARDS MUST MEET OR EXCEED UL94-V0 REQUIREMENTS." at 11361,2139.57 h60
  text "PCB MUST BEAR THE UL94V-0 UL REGISTERED MATERIAL ID NUMBER" at 11361,2023.5 h60
  text "ADDITIONAL REQUIREMENTS:" at 11333.46,1854.08 h60
  text "MICROSECTION:" at 11408.23,1746.95 h60
  text "YES" at 12313.96,1746.95 h60
  text "REQUIRED" at 13175.46,1602.62 h60
  text "BARE BOARD ELEC. TEST:" at 11408.23,1599.76 h60
  text "NONE" at 12713.96,1599.76 h60
  text "X" at 13057.46,1599.76 h60
  text "PER ORDER" at 13767.46,1599.76 h60
  text "XX MIL VIAS REQUIRE NON-CONDUCTIVE FILL AND PLANARIZE" at 11576.38,1394.82 h59
  text "XX MIL VIAS REQUIRE CONDUCTIVE FILL AND PLANARIZE" at 11584.38,1290.84 h60
  text "OUTER XX MIL TRACES REQUIRE 50 OHM SINGLE-ENDED IMPEDANCE" at 11583.39,1127.46 h58
  text "LAYER 2 & 3 (INNER LAYERS) XX MIL WIDE, XX MIL SPACE / TRACES REQUIRE 100 OHM DIFFERENTIAL IMPEDANCE" at 11575.39,891.74 h60
  text ".Layer_Name" at 577,-858.49 h60
M11 Gerber Information:
  lines w10: -292,-930.17 6308,-930.17 ; -292,-726.83 6310,-726.83 ; -292,-523.5 -292,-1133.5 3713,-1133.5 6310,-1133.5 6310,-523.5 -291.5,-523.5 -291.5,-1133.5 1284,-1133.5 ; 2173,-1133.5 2173,-523.5 ; 3440,-726.83 3440,-523.5 ; 4280,-726.83 4280,-523.5 ; 4902,-1140 4902,-937.17
  text "ALL ARTWORK VIEWED FROM TOP SIDE" at -228.5,-655.67 h60
  text "BOARD #:" at 2248,-655.67 h60
  text ".PRJ_Number" at 2793.5,-655.67 h60
  text "REV:" at 3638,-655.67 h60
  text ".PCB_Rev" at 3929.5,-655.67 h60
  text "SVN REV:" at 4476,-655.67 h60
  text ".VersionControl_RevNumber" at 4982,-655.67 h60
  text "LAYER NAME =" at -228.5,-858.49 h60
  text "TID #:" at 2248,-859 h60
  text ".TID" at 2793.5,-859 h60
  text "PLOT NAME =" at -228.5,-1064.34 h60
  text ".plot_File_Name" at 577,-1064.34 h60
  text "GENERATED    :" at 2250,-1064.34 h60
  text ".Print_Date" at 3119.5,-1064.34 h60
  text ".Print_Time" at 3848.5,-1064.34 h60
  text "TEXAS INSTRUMENTS" at 5113,-1064.34 h60
M12 Stackup:
  drawing of 399 lines, arcs and shapes, not listed
  text "Layer" at 9811.59,7604.94 h60
  text "Name" at 10221.51,7604.94 h60
  text "Material" at 11161.25,7604.94 h60
  text "Thickness" at 12021.02,7604.94 h60
  text "Constant" at 12670.85,7604.94 h60
  text "Board Layer Stack" at 13240.71,7604.94 h60
  text "1" at 9811.59,7484.94 h60
  text "Top Overlay" at 10221.51,7484.94 h60
  text "2" at 9811.59,7364.94 h60
  text "Top Solder" at 10221.51,7364.94 h60
  text "Solder Resist" at 11161.25,7364.94 h60
  text "0.50mil" at 12021.02,7364.94 h60
  text "3.5" at 12670.85,7364.94 h60
  text "3" at 9811.59,7244.94 h60
  text "Top Layer" at 10221.51,7244.94 h60
  text "Copper" at 11161.25,7244.94 h60
  text "2.80mil" at 12021.02,7244.94 h60
  text "4" at 9811.59,7124.94 h60
  text "Dielectric 1" at 10221.51,7124.94 h60
  text "FR-4 High Tg" at 11161.25,7124.94 h60
  text "7.00mil" at 12021.02,7124.94 h60
  text "4.2" at 12670.85,7124.94 h60
  text "5" at 9811.59,7004.94 h60
  text "Signal Layer 1" at 10221.51,7004.94 h60
  text "Copper" at 11161.25,7004.94 h60
  text "2.80mil" at 12021.02,7004.94 h60
  text "6" at 9811.59,6884.94 h60
  text "Dielectric 2" at 10221.51,6884.94 h60
  text "FR-4 High Tg" at 11161.25,6884.94 h60
  text "14.00mil" at 12021.02,6884.94 h60
  text "4.2" at 12670.85,6884.94 h60
  text "7" at 9811.59,6764.94 h60
  text "Signal Layer 2" at 10221.51,6764.94 h60
  text "Copper" at 11161.25,6764.94 h60
  text "2.80mil" at 12021.02,6764.94 h60
  text "8" at 9811.59,6644.94 h60
  text "Dielectric 4" at 10221.51,6644.94 h60
  text "FR-4 High Tg" at 11161.25,6644.94 h60
  text "11.00mil" at 12021.02,6644.94 h60
  text "4.2" at 12670.85,6644.94 h60
  text "9" at 9811.59,6524.94 h60
  text "Signal Layer 3" at 10221.51,6524.94 h60
  text "Copper" at 11161.25,6524.94 h60
  text "2.80mil" at 12021.02,6524.94 h60
  text "10" at 9811.59,6404.94 h60
  text "Dielectric 5" at 10221.51,6404.94 h60
  text "FR-4 High Tg" at 11161.25,6404.94 h60
  text "14.00mil" at 12021.02,6404.94 h60
  text "4.2" at 12670.85,6404.94 h60
  text "11" at 9811.59,6284.94 h60
  text "Signal Layer 4" at 10221.51,6284.94 h60
  text "Copper" at 11161.25,6284.94 h60
  text "2.80mil" at 12021.02,6284.94 h60
  text "12" at 9811.59,6164.94 h60
  text "Dielectric 3" at 10221.51,6164.94 h60
  text "FR-4 High Tg" at 11161.25,6164.94 h60
  text "7.00mil" at 12021.02,6164.94 h60
  text "4.2" at 12670.85,6164.94 h60
  text "13" at 9811.59,6044.94 h60
  text "Bottom Layer" at 10221.51,6044.94 h60
  text "Copper" at 11161.25,6044.94 h60
  text "2.80mil" at 12021.02,6044.94 h60
  text "14" at 9811.59,5924.94 h60
  text "Bottom Solder" at 10221.51,5924.94 h60
  text "Solder Resist" at 11161.25,5924.94 h60
  text "0.50mil" at 12021.02,5924.94 h60
  text "3.5" at 12670.85,5924.94 h60
  text "15" at 9811.59,5804.94 h60
  text "Bottom Overlay" at 10221.51,5804.94 h60
  text ".Layer_Name" at 577,-858.49 h60
M13 Component Bodies Top:
  text ".Layer_Name" at 577,-858.49 h60
M14 Component Bodies Bottom:
  text ".Layer_Name" at 577,-858.49 h60
M15 Courtyards Top:
  text ".Layer_Name" at 577,-858.49 h60
M16 Courtyards Bottom:
  text ".Layer_Name" at 577,-858.49 h60
Drill Drawing:
  circle w10: c5363.72,2865 r27.63
  lines w10: 5336.09,2961.7 5391.34,2961.7 5391.34,3016.95 5336.09,3016.95 5336.09,2961.7 ; 5336.09,3099.83 5349.9,3099.83 5363.72,3086.02 5377.53,3099.83 5391.34,3099.83 5377.53,3113.64 5391.34,3127.46 5377.53,3127.46 5363.72,3141.27 5349.9,3127.46 5336.09,3127.46 5349.9,3113.64 5336.09,3099.83 ; 5336.09,3265.59 5391.34,3265.59 5363.72,3210.34 5336.09,3265.59 ; 5336.09,3334.66 5363.72,3348.47 5391.34,3334.66 5377.53,3362.28 5391.34,3389.91 5363.72,3376.1 5336.09,3389.91 5349.9,3362.28 5336.09,3334.66
  lines w12: 5286,2800.08 8517.49,2800.08 ; 5286,3421.68 8517.49,3421.68 ; 5623.86,2675.76 5623.86,3546 ; 5955.86,2675.76 5955.86,3546 ; 6592.43,2675.76 6592.43,3546 ; 6851.57,2675.76 6851.57,3546 ; 7226.72,2675.76 7226.72,3546 ; 7951.05,2675.76 7951.05,3546 ; 5286,2675.76 8517.49,2675.76 8517.49,3546 5286,3546 5286,2675.76
  text "Symbol" at 5360.59,3458.98 h72
  text "Quantity" at 5661.16,3458.98 h72
  text "Finished Hole Size" at 5993.16,3458.98 h72
  text "Plated" at 6629.72,3458.98 h72
  text "Hole Type" at 6888.86,3458.98 h72
  text "Drill Layer Pair" at 7264.02,3458.98 h72
  text "Hole Tolerance" at 7988.35,3458.98 h72
  text "568" at 5661.16,3334.66 h60
  text "7.87mil (0.200mm)" at 5993.16,3334.66 h60
  text "PTH" at 6629.72,3334.66 h60
  text "Round" at 6888.86,3334.66 h60
  text "Top Layer - Bottom Layer" at 7264.02,3334.66 h60
  text "175" at 5661.16,3210.34 h60
  text "10.00mil (0.254mm)" at 5993.16,3210.34 h60
  text "PTH" at 6629.72,3210.34 h60
  text "Round" at 6888.86,3210.34 h60
  text "Top Layer - Bottom Layer" at 7264.02,3210.34 h60
  text "32" at 5661.16,3086.02 h60
  text "12.00mil (0.305mm)" at 5993.16,3086.02 h60
  text "PTH" at 6629.72,3086.02 h60
  text "Round" at 6888.86,3086.02 h60
  text "Top Layer - Bottom Layer" at 7264.02,3086.02 h60
  text "2" at 5661.16,2961.7 h60
  text "39.37mil (1.000mm)" at 5993.16,2961.7 h60
  text "PTH" at 6629.72,2961.7 h60
  text "Round" at 6888.86,2961.7 h60
  text "Top Layer - Bottom Layer" at 7264.02,2961.7 h60
  text "2" at 5661.16,2837.38 h60
  text "125.98mil (3.200mm)" at 5993.16,2837.38 h60
  text "PTH" at 6629.72,2837.38 h60
  text "Round" at 6888.86,2837.38 h60
  text "Top Layer - Bottom Layer" at 7264.02,2837.38 h60
  text "779 Total" at 5661.16,2713.06 h60
  text ".Layer_Name" at 577,-858.49 h60
M17 Embedded Cavity:
  text ".Layer_Name" at 577,-858.49 h60
M18 Embedded Assembly:
  text ".Layer_Name" at 577,-858.49 h60
M19 Embedded Keepout:
  text ".Layer_Name" at 577,-858.49 h60

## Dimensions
0,-400 to 1000,-400 on M2 Board Dimensions
0,0 to 0,1417.32 on M2 Board Dimensions
0,0 to 2440.95,157.48 on M2 Board Dimensions
2440.95,157.48 to 2130.94,311.06 on M2 Board Dimensions
2440.95,157.48 to 2509.84,431.06 on M2 Board Dimensions
2440.95,1417.32 to 960.44,1360.43 on M2 Board Dimensions
0,1417.32 to 757.87,1287.09 on M2 Board Dimensions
